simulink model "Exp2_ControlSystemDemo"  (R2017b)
settings: Solver=ode4  StartTime=0.0  StopTime=2000  FixedStep=0.001  RelTol=1e-3
PreLoadFcn:
  | filepath  = fileparts(get_param(bdroot, 'FileName'))
  | cd(filepath);
InitFcn:
  | if exist('Init_control.m','file')
  |      Init_control;
  | end
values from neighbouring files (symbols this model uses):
  KiPitchAttitude = 0.0552303199591522 / kFactor    (= 0.0460252666326)    [Init_control.m]
  KiPitchRate = 0.460338699849681 / kFactor    (= 0.383615583208)    [Init_control.m]
  KiRollAttitude = 0.0552303199591522 / kFactor    (= 0.0460252666326)    [Init_control.m]
  KiRollRate = 0.460338699849681 / kFactor    (= 0.383615583208)    [Init_control.m]
  KiYawRate = 0.460338699849681 / kFactor * 2    (= 0.767231166416)    [Init_control.m]
  KpPitchAttitude = 0.630138625117681 / kFactor    (= 0.525115520931)    [Init_control.m]
  KpPitchRate = 1.31533836563383 / kFactor    (= 1.09611530469)    [Init_control.m]
  KpRollAttitude = 0.630138625117681 / kFactor    (= 0.525115520931)    [Init_control.m]
  KpRollRate = 1.31533836563383 / kFactor    (= 1.09611530469)    [Init_control.m]
  KpYawRate = 1.31533836563383 / kFactor * 2    (= 2.19223060939)    [Init_control.m]
  ModelInit_RPM = 0    [Init.m]
  ModelParam_envAltitude = -50    [Init.m]
  ModelParam_GlobalNoiseGainSwitch = 0.4    [Init.m]
  ModelParam_GPSEphFinal = 0.3    [Init.m]
  ModelParam_GPSEpvFinal = 0.4    [Init.m]
  ModelParam_GPSFix3DFix = 3    [Init.m]
  ModelParam_GPSSatsVisible = 10    [Init.m]
  ModelParam_motorCr = 842.1    [Init.m]
  ModelParam_motorJm = 0.0001287    [Init.m]
  ModelParam_motorMinThr = 0.05    [Init.m]
  ModelParam_motorT = 0.0214    [Init.m]
  ModelParam_motorWb = 22.83    [Init.m]
  ModelParam_noiseBaroCoupleWithSpeed = 0    [Init.m]
  ModelParam_noiseGPSSampTime = 0.2    [Init.m]
  ModelParam_noisePowerIMU = 0    [Init.m]
  ModelParam_noisePowerOffGainAccel = 0.04    [Init.m]
  ModelParam_noisePowerOffGainAccelZ = 0.03    [Init.m]
  ModelParam_noisePowerOffGainGyro = 0.02    [Init.m]
  ModelParam_noisePowerOffGainGyroZ = 0.025    [Init.m]
  ModelParam_noisePowerOffGainMag = 0.02    [Init.m]
  ModelParam_noisePowerOffGainMagZ = 0.035    [Init.m]
  ModelParam_noisePowerOnGainAccel = 0.8    [Init.m]
  ModelParam_noisePowerOnGainAccelZ = 4.5    [Init.m]
  ModelParam_noisePowerOnGainGyro = 2    [Init.m]
  ModelParam_noisePowerOnGainGyroZ = 1    [Init.m]
  ModelParam_noisePowerOnGainMag = 0.025    [Init.m]
  ModelParam_noisePowerOnGainMagZ = 0.05    [Init.m]
  ModelParam_noiseSampleTimeAccel = 0.001    [Init.m]
  ModelParam_noiseSampleTimeGyro = 0.001    [Init.m]
  ModelParam_noiseSampleTimeMag = 0.01    [Init.m]
  ModelParam_noiseUpperGPS = 0.5    [Init.m]
  ModelParam_noiseUpperWindBodyRatio = 0    [Init.m]
  ModelParam_noiseWindSampTime = 0.001    [Init.m]
  ModelParam_rotorCm = 2.783e-07    [Init.m]
  ModelParam_rotorCt = 1.681e-05    [Init.m]
  ModelParam_timeSampBaro = 0.01    [Init.m]
  ModelParam_uavCCm = [0.0035 0.0039 0.0034]    [Init.m]
  ModelParam_uavCd = 0.055    [Init.m]
  ModelParam_uavDearo = 0.12    [Init.m]
  ModelParam_uavMass = 1.515    [Init.m]
  ModelParam_uavR = 0.225    [Init.m]
  ModelParam_uavType = int8(3)    [Init.m]
undefined symbols (not defined in the file or in its folder): a029, a452, a6b4, b2ca, be23, d291, d_i, da57f061, e227219c210b, e95a516b5039, Earth, earthRadius, Exp2_ControlSystemDemo, f0d8, f8138af1, ff54be59cd06, h_i, ModelParam_GPSEpvInitial, ModelParam_GPSEpvTimeConstant, ModelParam_noiseLowPassFilterCoeAccel, ModelParam_noiseLowPassFilterCoeGyro, ModelParam_timeSamp, Newton, Raphson, Receive, Send, slider, WGS84
libraries: simulink x17, aerolibfltsims x4, aerolibtransform2 x3, sharedtransform x3, aerolibasang x3, aerolibatmos2 x2, sharedutil x2, aerolibutil x2, etargetslib x2, shared6dof x1, aerolibconvert2 x1, aerolibobsolete x1
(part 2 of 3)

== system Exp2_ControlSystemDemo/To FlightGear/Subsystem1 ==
  copterID : Inport  PortDimensions=1
  vehicleType : Inport  Port=2  PortDimensions=1
  PosE : Inport  Port=3  PortDimensions=3
  AngEuler : Inport  Port=4  PortDimensions=3
  pwms : Inport  Port=5
  Clock : Clock
  Constant{,3..5} (4 alike) : Constant  Value=[0,0,0]
  Constant1 : Constant  Value=[0,0,0,0]
  Subsystem : Subsystem
  toUnReal : Outport
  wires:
  Constant/1 -> Subsystem/4("VelE ")
  PosE/1 -> Subsystem/5(PosE)
  vehicleType/1 -> Subsystem/2(vehicleType)
  Clock/1 -> Subsystem/3(runnedTime)
  Constant4/1 -> Subsystem/10(RateB)
  Constant5/1 -> Subsystem/11(PosGPS)
  AngEuler/1 -> Subsystem/6(AngEuler)
  Subsystem/1(toUnReal) -> toUnReal/1
  Constant3/1 -> Subsystem/9(AccB)
  Constant1/1 -> Subsystem/7(AngQuatern)
  copterID/1 -> Subsystem/1(copterID)
  pwms/1 -> Subsystem/8(MotorRPMS)

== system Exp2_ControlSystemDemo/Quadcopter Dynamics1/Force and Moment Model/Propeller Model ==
  uavType : Inport
  MotorRads : Inport  Port=2
  uavR : Inport  Port=3
  uavDearo : Inport  Port=4
  Cm : Inport  Port=5
  Ct : Inport  Port=6
  Jm : Inport  Port=7
  wb : Inport  Port=8
  Vb : Inport  Port=9
  Cd : Inport  Port=10
  Car : Subsystem  TreatAsAtomicUnit=on
  If : If  IfExpression=u1 >= 50
  Multicopter : Subsystem  TreatAsAtomicUnit=on
  Switch : Switch  Threshold=50
  Switch1 : Switch  Threshold=50
  Terminator : Terminator
  Terminator1 : Terminator
  Fb : Outport
  Mb : Outport  Port=2
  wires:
  Vb/1 -> Terminator/1
  Cd/1 -> Terminator1/1
  uavType/1 -> If/1, Switch/2, Switch1/2, Multicopter/1(uavType)
  Switch/1 -> Fb/1
  Switch1/1 -> Mb/1
  If/2 -> Multicopter/Action
  If/1 -> Car/Action
  Car/1(Fb) -> Switch/1
  Multicopter/1(Fb) -> Switch/3
  Car/2(Mb) -> Switch1/1
  Multicopter/2(Mb) -> Switch1/3
  MotorRads/1 -> Car/1(MotorRads), Multicopter/2(MotorRads)
  uavDearo/1 -> Multicopter/4(uavDearo)
  Cm/1 -> Multicopter/5(Cm)
  Ct/1 -> Multicopter/6(Ct)
  Jm/1 -> Multicopter/7(Jm)
  wb/1 -> Multicopter/8(wb)
  uavR/1 -> Multicopter/3(uavR)

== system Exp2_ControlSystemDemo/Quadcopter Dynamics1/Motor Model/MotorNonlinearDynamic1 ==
  Wb : Inport
  Cr : Inport  Port=2
  motorT : Inport  Port=3
  ModelInit_RPM : Inport  Port=4
  PWM : Inport  Port=5
  Minimum Throttle Cutoff : simulink/Logic and Bit Operations/Compare To Constant  relop=>=  const=ModelParam_motorMinThr  OutDataTypeStr=uint8
  Motor_Dynamics : Subsystem  TreatAsAtomicUnit=on
  Motor_Dynamics_backup : StateSpace  Commented=on  A=-1/ModelParam_motorT  C=1/ModelParam_motorT  D=0  InitialCondition=ModelInit_RPM*ModelParam_motorT
  Product : Product
  Product1 : Product
  Signal_Saturation : Saturate  UpperLimit=0.95  LowerLimit=0
  Sum1 : Sum  Inputs=++|
  radW : Outport
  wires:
  PWM/1 -> Signal_Saturation/1
  Motor_Dynamics/1(motor_rate_act) -> radW/1
  Product/1 -> Motor_Dynamics/1(motor_rate_d)
  Signal_Saturation/1 -> Product1/2, Minimum Throttle Cutoff/1
  Product1/1 -> Sum1/2
  Sum1/1 -> Product/1
  Wb/1 -> Sum1/1
  Minimum Throttle Cutoff/1 -> Product/2
  Cr/1 -> Product1/1
  motorT/1 -> Motor_Dynamics/3(motorT)
  ModelInit_RPM/1 -> Motor_Dynamics/2(ModelInit_RPM)

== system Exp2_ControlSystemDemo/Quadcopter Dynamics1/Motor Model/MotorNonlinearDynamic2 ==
  Wb : Inport
  Cr : Inport  Port=2
  motorT : Inport  Port=3
  ModelInit_RPM : Inport  Port=4
  PWM : Inport  Port=5
  Minimum Throttle Cutoff : simulink/Logic and Bit Operations/Compare To Constant  relop=>=  const=ModelParam_motorMinThr  OutDataTypeStr=uint8
  Motor_Dynamics : Subsystem  TreatAsAtomicUnit=on
  Motor_Dynamics_backup : StateSpace  Commented=on  A=-1/ModelParam_motorT  C=1/ModelParam_motorT  D=0  InitialCondition=ModelInit_RPM*ModelParam_motorT
  Product : Product
  Product1 : Product
  Signal_Saturation : Saturate  UpperLimit=0.95  LowerLimit=0
  Sum1 : Sum  Inputs=++|
  radW : Outport
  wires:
  ModelInit_RPM/1 -> Motor_Dynamics/2(ModelInit_RPM)
  motorT/1 -> Motor_Dynamics/3(motorT)
  Cr/1 -> Product1/1
  Minimum Throttle Cutoff/1 -> Product/2
  Wb/1 -> Sum1/1
  Sum1/1 -> Product/1
  Product1/1 -> Sum1/2
  Signal_Saturation/1 -> Minimum Throttle Cutoff/1, Product1/2
  Product/1 -> Motor_Dynamics/1(motor_rate_d)
  Motor_Dynamics/1(motor_rate_act) -> radW/1
  PWM/1 -> Signal_Saturation/1

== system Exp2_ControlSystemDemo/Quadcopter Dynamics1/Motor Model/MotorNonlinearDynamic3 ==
  Wb : Inport
  Cr : Inport  Port=2
  motorT : Inport  Port=3
  ModelInit_RPM : Inport  Port=4
  PWM : Inport  Port=5
  Minimum Throttle Cutoff : simulink/Logic and Bit Operations/Compare To Constant  relop=>=  const=ModelParam_motorMinThr  OutDataTypeStr=uint8
  Motor_Dynamics : Subsystem  TreatAsAtomicUnit=on
  Motor_Dynamics_backup : StateSpace  Commented=on  A=-1/ModelParam_motorT  C=1/ModelParam_motorT  D=0  InitialCondition=ModelInit_RPM*ModelParam_motorT
  Product : Product
  Product1 : Product
  Signal_Saturation : Saturate  UpperLimit=0.95  LowerLimit=0
  Sum1 : Sum  Inputs=++|
  radW : Outport
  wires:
  PWM/1 -> Signal_Saturation/1
  Motor_Dynamics/1(motor_rate_act) -> radW/1
  Product/1 -> Motor_Dynamics/1(motor_rate_d)
  Signal_Saturation/1 -> Product1/2, Minimum Throttle Cutoff/1
  Product1/1 -> Sum1/2
  Sum1/1 -> Product/1
  Wb/1 -> Sum1/1
  Minimum Throttle Cutoff/1 -> Product/2
  Cr/1 -> Product1/1
  motorT/1 -> Motor_Dynamics/3(motorT)
  ModelInit_RPM/1 -> Motor_Dynamics/2(ModelInit_RPM)

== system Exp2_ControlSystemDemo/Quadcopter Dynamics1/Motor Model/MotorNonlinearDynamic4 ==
  Wb : Inport
  Cr : Inport  Port=2
  motorT : Inport  Port=3
  ModelInit_RPM : Inport  Port=4
  PWM : Inport  Port=5
  Minimum Throttle Cutoff : simulink/Logic and Bit Operations/Compare To Constant  relop=>=  const=ModelParam_motorMinThr  OutDataTypeStr=uint8
  Motor_Dynamics : Subsystem  TreatAsAtomicUnit=on
  Motor_Dynamics_backup : StateSpace  Commented=on  A=-1/ModelParam_motorT  C=1/ModelParam_motorT  D=0  InitialCondition=ModelInit_RPM*ModelParam_motorT
  Product : Product
  Product1 : Product
  Signal_Saturation : Saturate  UpperLimit=0.95  LowerLimit=0
  Sum1 : Sum  Inputs=++|
  radW : Outport
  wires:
  ModelInit_RPM/1 -> Motor_Dynamics/2(ModelInit_RPM)
  motorT/1 -> Motor_Dynamics/3(motorT)
  Cr/1 -> Product1/1
  Minimum Throttle Cutoff/1 -> Product/2
  Wb/1 -> Sum1/1
  Sum1/1 -> Product/1
  Product1/1 -> Sum1/2
  Signal_Saturation/1 -> Minimum Throttle Cutoff/1, Product1/2
  Product/1 -> Motor_Dynamics/1(motor_rate_d)
  Motor_Dynamics/1(motor_rate_act) -> radW/1
  PWM/1 -> Signal_Saturation/1

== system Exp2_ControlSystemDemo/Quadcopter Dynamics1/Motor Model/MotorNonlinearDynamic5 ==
  Wb : Inport
  Cr : Inport  Port=2
  motorT : Inport  Port=3
  ModelInit_RPM : Inport  Port=4
  PWM : Inport  Port=5
  Minimum Throttle Cutoff : simulink/Logic and Bit Operations/Compare To Constant  relop=>=  const=ModelParam_motorMinThr  OutDataTypeStr=uint8
  Motor_Dynamics : Subsystem  TreatAsAtomicUnit=on
  Motor_Dynamics_backup : StateSpace  Commented=on  A=-1/ModelParam_motorT  C=1/ModelParam_motorT  D=0  InitialCondition=ModelInit_RPM*ModelParam_motorT
  Product : Product
  Product1 : Product
  Signal_Saturation : Saturate  UpperLimit=0.95  LowerLimit=0
  Sum1 : Sum  Inputs=++|
  radW : Outport
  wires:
  PWM/1 -> Signal_Saturation/1
  Motor_Dynamics/1(motor_rate_act) -> radW/1
  Product/1 -> Motor_Dynamics/1(motor_rate_d)
  Signal_Saturation/1 -> Product1/2, Minimum Throttle Cutoff/1
  Product1/1 -> Sum1/2
  Sum1/1 -> Product/1
  Wb/1 -> Sum1/1
  Minimum Throttle Cutoff/1 -> Product/2
  Cr/1 -> Product1/1
  motorT/1 -> Motor_Dynamics/3(motorT)
  ModelInit_RPM/1 -> Motor_Dynamics/2(ModelInit_RPM)

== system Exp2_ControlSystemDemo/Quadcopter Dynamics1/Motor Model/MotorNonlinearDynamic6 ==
  Wb : Inport
  Cr : Inport  Port=2
  motorT : Inport  Port=3
  ModelInit_RPM : Inport  Port=4
  PWM : Inport  Port=5
  Minimum Throttle Cutoff : simulink/Logic and Bit Operations/Compare To Constant  relop=>=  const=ModelParam_motorMinThr  OutDataTypeStr=uint8
  Motor_Dynamics : Subsystem  TreatAsAtomicUnit=on
  Motor_Dynamics_backup : StateSpace  Commented=on  A=-1/ModelParam_motorT  C=1/ModelParam_motorT  D=0  InitialCondition=ModelInit_RPM*ModelParam_motorT
  Product : Product
  Product1 : Product
  Signal_Saturation : Saturate  UpperLimit=0.95  LowerLimit=0
  Sum1 : Sum  Inputs=++|
  radW : Outport
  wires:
  ModelInit_RPM/1 -> Motor_Dynamics/2(ModelInit_RPM)
  motorT/1 -> Motor_Dynamics/3(motorT)
  Cr/1 -> Product1/1
  Minimum Throttle Cutoff/1 -> Product/2
  Wb/1 -> Sum1/1
  Sum1/1 -> Product/1
  Product1/1 -> Sum1/2
  Signal_Saturation/1 -> Minimum Throttle Cutoff/1, Product1/2
  Product/1 -> Motor_Dynamics/1(motor_rate_d)
  Motor_Dynamics/1(motor_rate_act) -> radW/1
  PWM/1 -> Signal_Saturation/1

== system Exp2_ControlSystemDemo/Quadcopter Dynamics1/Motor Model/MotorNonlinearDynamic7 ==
  Wb : Inport
  Cr : Inport  Port=2
  motorT : Inport  Port=3
  ModelInit_RPM : Inport  Port=4
  PWM : Inport  Port=5
  Minimum Throttle Cutoff : simulink/Logic and Bit Operations/Compare To Constant  relop=>=  const=ModelParam_motorMinThr  OutDataTypeStr=uint8
  Motor_Dynamics : Subsystem  TreatAsAtomicUnit=on
  Motor_Dynamics_backup : StateSpace  Commented=on  A=-1/ModelParam_motorT  C=1/ModelParam_motorT  D=0  InitialCondition=ModelInit_RPM*ModelParam_motorT
  Product : Product
  Product1 : Product
  Signal_Saturation : Saturate  UpperLimit=0.95  LowerLimit=0
  Sum1 : Sum  Inputs=++|
  radW : Outport
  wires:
  PWM/1 -> Signal_Saturation/1
  Motor_Dynamics/1(motor_rate_act) -> radW/1
  Product/1 -> Motor_Dynamics/1(motor_rate_d)
  Signal_Saturation/1 -> Product1/2, Minimum Throttle Cutoff/1
  Product1/1 -> Sum1/2
  Sum1/1 -> Product/1
  Wb/1 -> Sum1/1
  Minimum Throttle Cutoff/1 -> Product/2
  Cr/1 -> Product1/1
  motorT/1 -> Motor_Dynamics/3(motorT)
  ModelInit_RPM/1 -> Motor_Dynamics/2(ModelInit_RPM)

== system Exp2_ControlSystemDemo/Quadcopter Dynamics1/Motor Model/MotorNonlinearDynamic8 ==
  Wb : Inport
  Cr : Inport  Port=2
  motorT : Inport  Port=3
  ModelInit_RPM : Inport  Port=4
  PWM : Inport  Port=5
  Minimum Throttle Cutoff : simulink/Logic and Bit Operations/Compare To Constant  relop=>=  const=ModelParam_motorMinThr  OutDataTypeStr=uint8
  Motor_Dynamics : Subsystem  TreatAsAtomicUnit=on
  Motor_Dynamics_backup : StateSpace  Commented=on  A=-1/ModelParam_motorT  C=1/ModelParam_motorT  D=0  InitialCondition=ModelInit_RPM*ModelParam_motorT
  Product : Product
  Product1 : Product
  Signal_Saturation : Saturate  UpperLimit=0.95  LowerLimit=0
  Sum1 : Sum  Inputs=++|
  radW : Outport
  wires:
  ModelInit_RPM/1 -> Motor_Dynamics/2(ModelInit_RPM)
  motorT/1 -> Motor_Dynamics/3(motorT)
  Cr/1 -> Product1/1
  Minimum Throttle Cutoff/1 -> Product/2
  Wb/1 -> Sum1/1
  Sum1/1 -> Product/1
  Product1/1 -> Sum1/2
  Signal_Saturation/1 -> Minimum Throttle Cutoff/1, Product1/2
  Product/1 -> Motor_Dynamics/1(motor_rate_d)
  Motor_Dynamics/1(motor_rate_act) -> radW/1
  PWM/1 -> Signal_Saturation/1

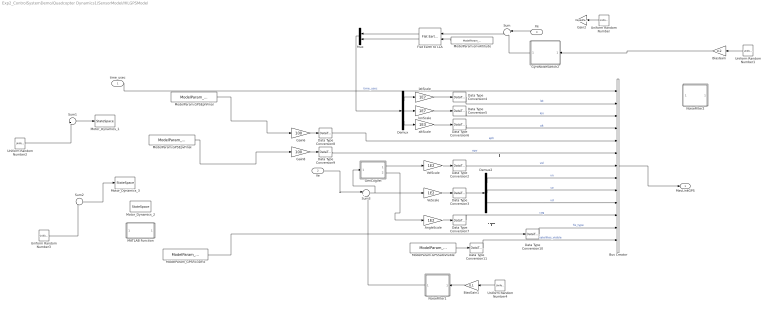
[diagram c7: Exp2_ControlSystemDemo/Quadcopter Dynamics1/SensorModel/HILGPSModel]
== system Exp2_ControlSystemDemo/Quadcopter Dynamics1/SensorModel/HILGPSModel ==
  note: 水平速度
  note: 运动方位
  time_usec : Inport
  Ve : Inport  Port=2
  Xe : Inport  Port=3
  AngleScale : Gain  Gain=1E2
  BiasGain : Gain  Gain=0.2
  BiasGain1 : Gain  Gain=0.1
  Bus Creator : BusCreator  Inputs=13  OutDataTypeStr=Bus: MavLinkGPS
  Data Type Conversion10 : DataTypeConversion  OutDataTypeStr=uint8  RndMeth=Round
  Data Type Conversion11 : DataTypeConversion  OutDataTypeStr=uint8  RndMeth=Round
  Data Type Conversion{2,7..9} (4 alike) : DataTypeConversion  OutDataTypeStr=uint16  RndMeth=Round
  Data Type Conversion3 : DataTypeConversion  OutDataTypeStr=int16  RndMeth=Round
  Data Type Conversion4 : DataTypeConversion  OutDataTypeStr=int32  RndMeth=Round
  Data Type Conversion5 : DataTypeConversion  OutDataTypeStr=int32  RndMeth=Round
  Data Type Conversion6 : DataTypeConversion  OutDataTypeStr=int32  RndMeth=Round
  Demux : Demux  Outputs=3
  Demux2 : Demux  Outputs=3
  Flat Earth to LLA : aerolibtransform2/Flat Earth to LLA  units=Metric (MKS)  ptype=Earth (WGS84)  F=1/298.257223563  R=6378137  LL0=ModelParam_GPSLatLong  psi=0
  Gain2 : Gain  Commented=on  Gain=ModelParam_noiseUpperGPS
  Gain6 : Gain  Gain=100
  Gain8 : Gain  Gain=100
  GenCogVel : MATLAB Function  TreatAsAtomicUnit=on
  GyroNoiseSwitch2 : Subsystem
  MATLAB Function : MATLAB Function  Commented=on  TreatAsAtomicUnit=on
  ModelParam.GPSEphFinal : Constant  Value=ModelParam_GPSEphFinal
  ModelParam.GPSEpvFinal : Constant  Value=ModelParam_GPSEpvFinal
  ModelParam.GPSSatsVisible : Constant  Value=ModelParam_GPSSatsVisible
  ModelParam.envAltitude : Constant  Value=ModelParam_envAltitude
  ModelParam_GPSFix3DFix : Constant  Value=ModelParam_GPSFix3DFix
  Motor_Dynamics_1 : StateSpace  Commented=on  A=-1/0.2  C=1/0.2  D=0  InitialCondition=20*0.2
  Motor_Dynamics_2 : StateSpace  Commented=on  A=-1/ModelParam_GPSEpvTimeConstant  C=1/ModelParam_GPSEpvTimeConstant  D=0  InitialCondition=ModelParam_GPSEpvInitial*ModelParam_GPSEpvTimeConstant
  Motor_Dynamics_3 : StateSpace  Commented=on  A=-1/0.2  C=1/0.2  D=0  InitialCondition=20*0.2
  Mux : Mux  Inputs=2
  NoiseFilter1 : Subsystem
  NoiseFilter2 : Subsystem  Commented=on
  Sum : Sum  Inputs=|++
  Sum1 : Sum  Commented=on  Inputs=|++
  Sum2 : Sum  Commented=on  Inputs=|++
  Sum3 : Sum  Inputs=|++
  Uniform Random Number : UniformRandomNumber  Commented=on  Minimum=[-1,-1,-3]  Maximum=[1,1,3]  Seed=[14524,7875,698]  SampleTime=ModelParam_timeSamp
  Uniform Random Number1 : UniformRandomNumber  Minimum=[-1,-1,-2]  Maximum=[1,1,2]  Seed=[1452,787,69]  SampleTime=ModelParam_noiseGPSSampTime
  Uniform Random Number2 : UniformRandomNumber  Commented=on  Minimum=-0.01  Maximum=0.01  Seed=4345454  SampleTime=ModelParam_noiseGPSSampTime
  Uniform Random Number3 : UniformRandomNumber  Commented=on  Seed=3244333  SampleTime=ModelParam_noiseGPSSampTime
  Uniform Random Number4 : UniformRandomNumber  Minimum=[-1,-1,-2]  Maximum=[1,1,2]  Seed=[5445,45433,33433]  SampleTime=ModelParam_noiseGPSSampTime
  VeScale : Gain  Gain=1E2
  VelScale : Gain  Gain=1E2
  altScale : Gain  Gain=1E3
  latScale : Gain  Gain=1E7
  lonScale : Gain  Gain=1E7
  MavLinkGPS : Outport
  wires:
  Data Type Conversion8/1 -> Bus Creator/5  "eph"
  Gain8/1 -> Data Type Conversion9/1
  Gain6/1 -> Data Type Conversion8/1
  Data Type Conversion9/1 -> Bus Creator/6  "epv"
  time_usec/1 -> Bus Creator/1  "time_usec"
  latScale/1 -> Data Type Conversion4/1
  lonScale/1 -> Data Type Conversion5/1
  altScale/1 -> Data Type Conversion6/1
  Data Type Conversion4/1 -> Bus Creator/2  "lat"
  Data Type Conversion5/1 -> Bus Creator/3  "lon"
  Data Type Conversion6/1 -> Bus Creator/4  "alt"
  Demux2/1 -> Bus Creator/8  "vn"
  Demux2/2 -> Bus Creator/9  "ve"
  Demux2/3 -> Bus Creator/10  "vd"
  VeScale/1 -> Data Type Conversion3/1
  Data Type Conversion3/1 -> Demux2/1
  VelScale/1 -> Data Type Conversion2/1
  Data Type Conversion2/1 -> Bus Creator/7  "vel"
  AngleScale/1 -> Data Type Conversion7/1
  Data Type Conversion7/1 -> Bus Creator/11  "cog"
  Data Type Conversion11/1 -> Bus Creator/13  "satellites_visible"
  Data Type Conversion10/1 -> Bus Creator/12  "fix_type"
  ModelParam.GPSSatsVisible/1 -> Data Type Conversion11/1
  Flat Earth to LLA/2 -> Mux/2
  ModelParam.envAltitude/1 -> Flat Earth to LLA/2
  Xe/1 -> Sum/1
  Flat Earth to LLA/1 -> Mux/1
  Demux/1 -> latScale/1
  Demux/2 -> lonScale/1
  Demux/3 -> altScale/1
  Uniform Random Number/1 -> Gain2/1
  Sum/1 -> Flat Earth to LLA/1
  Uniform Random Number1/1 -> BiasGain/1
  BiasGain/1 -> GyroNoiseSwitch2/1(In1)
  Mux/1 -> Demux/1
  ModelParam.GPSEphFinal/1 -> Gain6/1
  Sum2/1 -> Motor_Dynamics_3/1
  ModelParam_GPSFix3DFix/1 -> Data Type Conversion10/1
  Ve/1 -> Sum3/1
  GenCogVel/1(v) -> VelScale/1
  GyroNoiseSwitch2/1(Out1) -> Sum/2
  Bus Creator/1 -> MavLinkGPS/1
  BiasGain1/1 -> NoiseFilter1/1(In1)
  Uniform Random Number4/1 -> BiasGain1/1
  GenCogVel/2(cot) -> AngleScale/1
  Sum1/1 -> Motor_Dynamics_1/1
  Uniform Random Number2/1 -> Sum1/2
  Uniform Random Number3/1 -> Sum2/2
  ModelParam.GPSEpvFinal/1 -> Gain8/1
  Sum3/1 -> GenCogVel/1(u), VeScale/1
  NoiseFilter1/1(Out1) -> Sum3/2

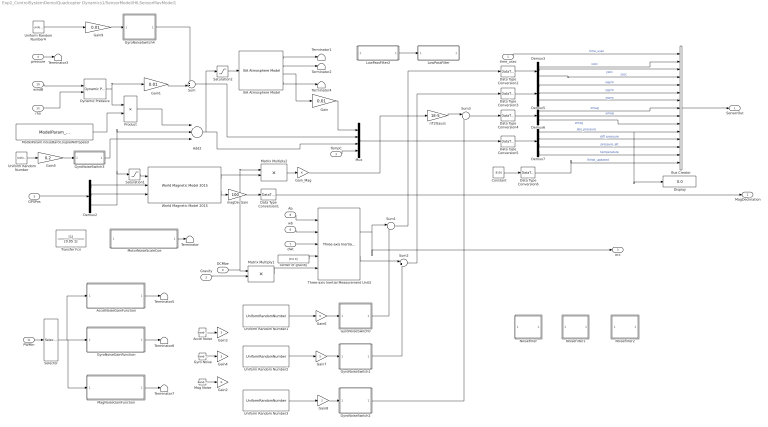
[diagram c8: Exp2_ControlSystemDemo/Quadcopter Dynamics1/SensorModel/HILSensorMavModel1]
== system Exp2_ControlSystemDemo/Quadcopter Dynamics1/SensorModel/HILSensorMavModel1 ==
  time_usec : Inport
  Gravity : Inport  Port=2
  TempC : Inport  Port=3
  pressure : Inport  Port=4
  GPSPos : Inport  Port=5
  wb : Inport  Port=6
  dwt : Inport  Port=7
  Ab : Inport  Port=8
  DCMbe : Inport  Port=9
  windB : Inport  Port=10
  PWMin : Inport  Port=11
  rho : Inport  Port=12
  Accel Noise : simulink/Sources/Band-Limited White Noise  Commented=on  Cov=ModelParam_noisePowerAccel  Ts=ModelParam_noiseSampleTimeAccel  seed=[411144,1416,71144]
  AccelNoiseGainFunction : MATLAB Function  TreatAsAtomicUnit=on
  Add2 : Sum  Inputs=+++
  Bus Creator : BusCreator  Inputs=15  OutDataTypeStr=Bus: MavLinkSensor
  Constant : Constant  Value=8191
  Data Type Conversion1 : DataTypeConversion  OutDataTypeStr=int16
  Data Type Conversion{2..5} (4 alike) : DataTypeConversion  OutDataTypeStr=single
  Data Type Conversion6 : DataTypeConversion  OutDataTypeStr=uint32
  Demux{2..3,5..6} (4 alike) : Demux  Outputs=3
  Demux7 : Demux
  Display : Display
  Dynamic Pressure : aerolibasang/Dynamic Pressure
  Gain : Gain  Gain=0.01
  Gain1 : Gain  Gain=0.01
  Gain2 : Gain  Commented=on
  Gain3 : Gain  Commented=on  Gain=3
  Gain4 : Gain  Commented=on  Gain=3
  Gain5 : Gain  Gain=0.2
  Gain6 : Gain  Gain=5
  Gain7 : Gain  Gain=5
  Gain8 : Gain  Gain=2
  Gain9 : Gain  Gain=0.01
  Gain_Mag : Gain
  Gyro Noise : simulink/Sources/Band-Limited White Noise  Commented=on  Cov=ModelParam_noisePowerGyro  Ts=ModelParam_noiseSampleTimeGyro  seed=[111,116,144]
  GyroNoiseGainFunction : MATLAB Function  TreatAsAtomicUnit=on
  GyroNoiseSwitch0 : Subsystem
  GyroNoiseSwitch1 : Subsystem
  GyroNoiseSwitch2 : Subsystem
  GyroNoiseSwitch3 : Subsystem
  GyroNoiseSwitch4 : Subsystem
  ISA Atmosphere Model : aerolibatmos2/ISA Atmosphere Model  custom=off  g=9.80665  gamma=1.4  R=287.0531  L=0.0065  h_trop=11000  h_strat=20000  rho0=1.225  P0=101325  T0=288.15  h0=0
  LowPassFilter : Subsystem  Commented=on
  LowPassFilter2 : Subsystem  Commented=on
  Mag Noise : simulink/Sources/Band-Limited White Noise  Commented=on  Cov=ModelParam_noisePowerMag  Ts=ModelParam_noiseSampleTimeMag  seed=[114,11699,999144]
  MagNoiseGainFunction : MATLAB Function  TreatAsAtomicUnit=on
  Matrix Multiply1 : Product  Multiplication=Matrix(*)
  Matrix Multiply2 : Product  Multiplication=Matrix(*)
  ModelParam.noiseBaroCoupleWithSpeed : Constant  Value=ModelParam_noiseBaroCoupleWithSpeed
  MotorNoiseScaleCoe : MATLAB Function  Commented=on  TreatAsAtomicUnit=on
  Mux : Mux
  NoiseFilter : Subsystem  Commented=on
  NoiseFilter1 : Subsystem  Commented=on
  NoiseFilter2 : Subsystem  Commented=on
  Product : Product
  Saturation1 : Saturate  UpperLimit=100000  LowerLimit=0
  Saturation2 : Saturate  UpperLimit=100000  LowerLimit=0
  Selector : Selector  InputPortWidth=8  IndexOptions=Index vector (dialog)  Indices=[1]  OutputSizes=1
  Sum : Sum  Inputs=++|
  Sum1 : Sum  Inputs=|++
  Sum2 : Sum  Inputs=|++
  Sum3 : Sum  Inputs=|++
  Terminator{,1..7} (8 alike) : Terminator
  Three-axis Inertial Measurement Unit3 : aerolibnav/Three-axis Inertial Measurement Unit  units=Metric (MKS)  imu=[0 0 0]  i_Ts=0  dtype_a=on  w_a=190  z_a=0.707  a_sf_cc=[1 0 0; 0 1 0; 0 0 1]  a_bias=[0 0 0]  a_sat="[-160  -160  -160 160 160 160]"  dtype_g=on  w_g=190  z_g=0.707  g_sf_cc=[1 0 0; 0 1 0; 0 0 1]  g_bias=[0 0 0]  g_sens=[0 0 0]  g_sat="[-4.36  -4.36  -4.36 4.36 4.36 4.36]"  i_rand=off  i_seeds=[23093 23094 23095 23096 23097 23098]  i_pow=ModelParam_noisePowerIMU*[0.0000005 0.0000005 0.0000005 0.000000002 0.000000002 0.000000002]
  Transfer Fcn : TransferFcn  Commented=on  Denominator=[0.05 1]
  Uniform Random Number : UniformRandomNumber  Minimum=-2  Maximum=2  Seed=15634  SampleTime=ModelParam_timeSampBaro
  Uniform Random Number1 : UniformRandomNumber  Minimum=-[0.1,0.1,0.2]  Maximum=[0.1,0.1,0.2]  Seed=[12233,645554,678766]  SampleTime=0.004
  Uniform Random Number2 : UniformRandomNumber  Minimum=-[0.01,0.01,0.01]  Maximum=[0.01,0.01,0.01]  Seed=[3243,44556,2334343]  SampleTime=0.004
  Uniform Random Number3 : UniformRandomNumber  Minimum=-[0.01,0.01,0.01]  Maximum=[0.01,0.01,0.01]  Seed=[45465,454534,1234232]  SampleTime=0.004
  Uniform Random Number4 : UniformRandomNumber  Seed=25634  SampleTime=0.01
  World Magnetic Model 2015 : aerolibgravity2/World Magnetic Model 2015  units=Metric (MKS)  time_in=off  month=November  day=3  year=2017  action=Error  h_out=off  dec_out=on  inc_out=off  ti_out=off
  center of gravity : Constant  Value=[0 0 0]
  magDecGain : Gain  Gain=100
  nT2Gauss : Gain  Gain=1E-5
  SensorOut : Outport
  MagDeclination : Outport  Port=2
  acc : Outport  Port=3
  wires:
  center of gravity/1 -> Three-axis Inertial Measurement Unit3/4
  Sum1/1 -> Data Type Conversion2/1
  Sum2/1 -> Data Type Conversion3/1
  Sum3/1 -> Data Type Conversion4/1
  Matrix Multiply2/1 -> Gain_Mag/1
  magDecGain/1 -> Data Type Conversion1/1
  World Magnetic Model 2015/2 -> magDecGain/1
  GyroNoiseSwitch3/1(Out1) -> Add2/3
  Product/1 -> Add2/1
  ModelParam.noiseBaroCoupleWithSpeed/1 -> Product/2
  rho/1 -> Dynamic Pressure/2
  windB/1 -> Dynamic Pressure/1
  Uniform Random Number/1 -> Gain5/1
  dwt/1 -> Three-axis Inertial Measurement Unit3/3
  Gain_Mag/1 -> nT2Gauss/1
  Dynamic Pressure/1 -> Gain1/1, Product/1
  pressure/1 -> Terminator3/1
  Add2/1 -> Mux/3, Saturation2/1
  Demux2/3 -> Saturation1/1, Add2/2
  Demux2/2 -> World Magnetic Model 2015/3
  Demux2/1 -> World Magnetic Model 2015/2
  Matrix Multiply1/1 -> Three-axis Inertial Measurement Unit3/5
  DCMbe/1 -> Matrix Multiply2/1, Matrix Multiply1/1
  Gravity/1 -> Matrix Multiply1/2
  Sum/1 -> Mux/2
  Gain/1 -> Mux/1
  Data Type Conversion6/1 -> Bus Creator/15  "fields_updated"
  Constant/1 -> Data Type Conversion6/1
  time_usec/1 -> Bus Creator/1  "time_usec"
  GPSPos/1 -> Demux2/1
  Demux7/2 -> Bus Creator/12  "diff_pressure"
  Demux7/3 -> Bus Creator/13  "pressure_alt"
  Demux6/2 -> Bus Creator/9  "ymag"
  Demux6/3 -> Bus Creator/10  "zmag"
  TempC/1 -> Mux/4
  Mux/1 -> Data Type Conversion5/1
  Demux7/1 -> Bus Creator/11, Display/1  "abs_pressure"
  Demux5/2 -> Bus Creator/6  "ygyro"
  Demux6/1 -> Bus Creator/8  "xmag"
  Demux5/3 -> Bus Creator/7  "zgyro"
  Demux7/4 -> Bus Creator/14  "temperature"
  World Magnetic Model 2015/1 -> Matrix Multiply2/2
  Demux3/1 -> Bus Creator/2  "xacc"
  Demux3/2 -> Bus Creator/3  "yacc"
  Demux5/1 -> Bus Creator/5  "xgyro"
  Demux3/3 -> Bus Creator/4  "zacc"
  PWMin/1 -> Selector/1
  Ab/1 -> Three-axis Inertial Measurement Unit3/1
  wb/1 -> Three-axis Inertial Measurement Unit3/2
  MotorNoiseScaleCoe/1(NoiseScaleCoe) -> Terminator/1
  Selector/1 -> AccelNoiseGainFunction/1(theta), MagNoiseGainFunction/1(theta), GyroNoiseGainFunction/1(theta)
  AccelNoiseGainFunction/1(Gain) -> Terminator5/1
  Mag Noise/1 -> Gain2/1
  nT2Gauss/1 -> Sum3/1
  Gain8/1 -> GyroNoiseSwitch2/1(In1)
  GyroNoiseSwitch1/1(Out1) -> Sum2/2
  GyroNoiseSwitch2/1(Out1) -> Sum3/2
  Data Type Conversion2/1 -> Demux3/1
  Data Type Conversion3/1 -> Demux5/1
  Data Type Conversion4/1 -> Demux6/1
  Data Type Conversion5/1 -> Demux7/1
  Bus Creator/1 -> SensorOut/1
  Data Type Conversion1/1 -> MagDeclination/1
  Three-axis Inertial Measurement Unit3/1 -> acc/1, Sum1/1
  Three-axis Inertial Measurement Unit3/2 -> Sum2/1
  ISA Atmosphere Model/2 -> Terminator2/1
  ISA Atmosphere Model/4 -> Terminator4/1
  ISA Atmosphere Model/1 -> Terminator1/1
  Gain5/1 -> GyroNoiseSwitch3/1(In1)
  Accel Noise/1 -> Gain3/1
  GyroNoiseSwitch0/1(Out1) -> Sum1/2
  Gyro Noise/1 -> Gain4/1
  GyroNoiseGainFunction/1(Gain) -> Terminator6/1
  MagNoiseGainFunction/1(Gain) -> Terminator7/1
  Uniform Random Number1/1 -> Gain6/1
  Gain7/1 -> GyroNoiseSwitch1/1(In1)
  Uniform Random Number2/1 -> Gain7/1
  Uniform Random Number3/1 -> Gain8/1
  ISA Atmosphere Model/3 -> Gain/1
  Gain6/1 -> GyroNoiseSwitch0/1(In1)
  LowPassFilter2/1(accelDataOut) -> LowPassFilter/1(gyroDataIn)
  Gain9/1 -> GyroNoiseSwitch4/1(In1)
  Uniform Random Number4/1 -> Gain9/1
  Gain1/1 -> Sum/2
  GyroNoiseSwitch4/1(Out1) -> Sum/1
  Saturation1/1 -> World Magnetic Model 2015/1
  Saturation2/1 -> ISA Atmosphere Model/1

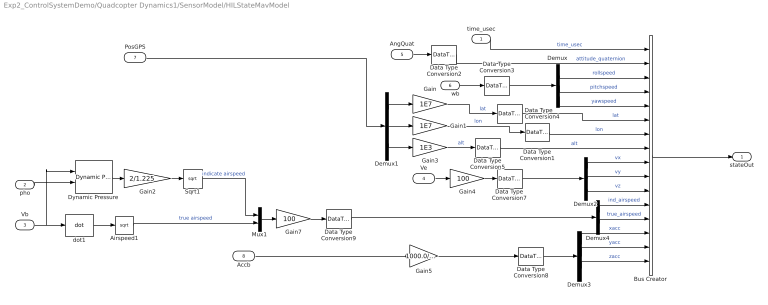
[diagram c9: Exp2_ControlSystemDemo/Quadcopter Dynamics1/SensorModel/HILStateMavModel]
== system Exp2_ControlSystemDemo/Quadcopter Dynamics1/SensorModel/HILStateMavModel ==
  time_usec : Inport
  pho : Inport  Port=2
  Vb : Inport  Port=3
  Ve : Inport  Port=4
  AngQuat : Inport  Port=5
  wb : Inport  Port=6
  PosGPS : Inport  Port=7
  Accb : Inport  Port=8
  Airspeed1 : Sqrt  AlgorithmType=Newton-Raphson
  Bus Creator : BusCreator  Inputs=16  OutDataTypeStr=Bus: MavLinkStateQuat
  Data Type Conversion1 : DataTypeConversion  OutDataTypeStr=int32  RndMeth=Round
  Data Type Conversion2 : DataTypeConversion  OutDataTypeStr=single
  Data Type Conversion3 : DataTypeConversion  OutDataTypeStr=single
  Data Type Conversion4 : DataTypeConversion  OutDataTypeStr=int32  RndMeth=Round
  Data Type Conversion5 : DataTypeConversion  OutDataTypeStr=int32  RndMeth=Round
  Data Type Conversion7 : DataTypeConversion  OutDataTypeStr=int16  RndMeth=Round
  Data Type Conversion8 : DataTypeConversion  OutDataTypeStr=int16  RndMeth=Round
  Data Type Conversion9 : DataTypeConversion  OutDataTypeStr=uint16  RndMeth=Round
  Demux{,1..3} (4 alike) : Demux  Outputs=3
  Demux4 : Demux  Outputs=2
  Dynamic Pressure : aerolibasang/Dynamic Pressure
  Gain : Gain  Gain=1E7
  Gain1 : Gain  Gain=1E7
  Gain2 : Gain  Gain=2/1.225
  Gain3 : Gain  Gain=1E3
  Gain4 : Gain  Gain=100
  Gain5 : Gain  Gain=1000.0/9.80665
  Gain7 : Gain  Gain=100
  Mux1 : Mux  Inputs=2
  Sqrt1 : Sqrt
  dot1 : aerolibasang/Incidence, Sideslip, & Airspeed/dot
  stateOut : Outport
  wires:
  Sqrt1/1 -> Mux1/1  "indicate airspeed"
  Gain2/1 -> Sqrt1/1
  Dynamic Pressure/1 -> Gain2/1
  time_usec/1 -> Bus Creator/1  "time_usec"
  Vb/1 -> dot1/1, Dynamic Pressure/1
  AngQuat/1 -> Data Type Conversion2/1
  Ve/1 -> Gain4/1
  wb/1 -> Data Type Conversion3/1
  Airspeed1/1 -> Mux1/2  "true airspeed"
  Mux1/1 -> Gain7/1
  Demux4/1 -> Bus Creator/12  "ind_airspeed"
  Demux4/2 -> Bus Creator/13  "true_airspeed"
  Demux3/3 -> Bus Creator/16  "zacc"
  Demux3/2 -> Bus Creator/15  "yacc"
  Demux3/1 -> Bus Creator/14  "xacc"
  Gain5/1 -> Data Type Conversion8/1
  Accb/1 -> Gain5/1
  Demux2/3 -> Bus Creator/11  "vz"
  Demux2/2 -> Bus Creator/10  "vy"
  Demux2/1 -> Bus Creator/9  "vx"
  Gain4/1 -> Data Type Conversion7/1
  Gain3/1 -> Data Type Conversion5/1  "alt"
  Gain1/1 -> Data Type Conversion1/1  "lon"
  Gain/1 -> Data Type Conversion4/1  "lat"
  Demux1/3 -> Gain3/1
  Demux1/2 -> Gain1/1
  Demux1/1 -> Gain/1
  Demux/3 -> Bus Creator/5  "yawspeed"
  Demux/2 -> Bus Creator/4  "pitchspeed"
  Demux/1 -> Bus Creator/3  "rollspeed"
  Data Type Conversion2/1 -> Bus Creator/2  "attitude_quaternion"
  pho/1 -> Dynamic Pressure/2
  Gain7/1 -> Data Type Conversion9/1
  dot1/1 -> Airspeed1/1
  Data Type Conversion3/1 -> Demux/1
  Data Type Conversion7/1 -> Demux2/1
  Data Type Conversion9/1 -> Demux4/1
  Data Type Conversion8/1 -> Demux3/1
  Data Type Conversion4/1 -> Bus Creator/6  "lat"
  Data Type Conversion1/1 -> Bus Creator/7  "lon"
  Data Type Conversion5/1 -> Bus Creator/8  "alt"
  Bus Creator/1 -> stateOut/1
  PosGPS/1 -> Demux1/1

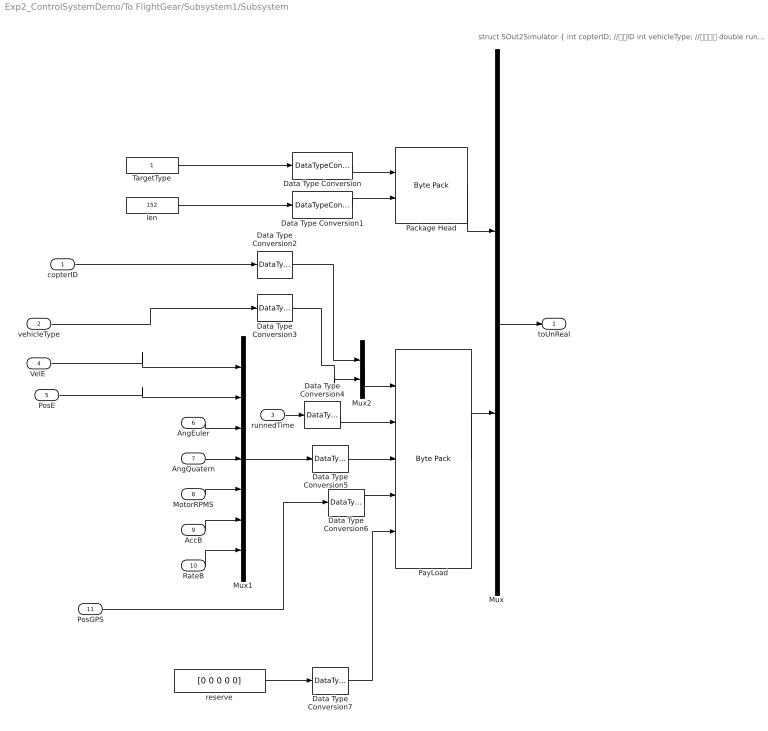
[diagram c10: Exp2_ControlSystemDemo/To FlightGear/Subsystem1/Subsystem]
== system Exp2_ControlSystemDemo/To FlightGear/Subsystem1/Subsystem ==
  note: struct SOut2Simulator { int copterID; //飞机ID int vehicleType; //飞机构型 double runnedTime; //仿真时间 float VelE[3]; //NED地球系速度 float PosE[3]; //NED地球系位置 float AngEuler[3]; //欧拉角 float AngQuatern[4]; //四元数 float MotorRPMS[8]; //电机转速RPM float AccB[3]; //机体轴加速度 float RateB[3]; //机体轴角速度 double PosGPS[3]; //地球GPS经纬高 } //SOut2Simulator的定义与Simulink里面新加的MavVehileInfo结构体完全一致 //可以直接对新的simulink模型的MavVehile3DInfo输出口数据进行打包 //两个结构体的长度都是152 sizeof(SOut2Simulator) = sizeof(MavVehileInfo) = 152 打包封装的结构体为 typedef struct _netDataShort { TargetType tg; //这里目前随便填，写1即可 uint32 int len; //这个长度为传输结构体长度，目前是152 char payload[192]; //这里面前152位存放了SOut2Simulator结构体数据，后面的40位保留 }netDataShort; //UDP包的总长度为200 sizeof(netDataShort) = 200 //发送的UDP端口号为：20010
  copterID : Inport  PortDimensions=1
  vehicleType : Inport  Port=2  PortDimensions=1
  runnedTime : Inport  Port=3  PortDimensions=1
  "VelE " : Inport  Port=4  PortDimensions=3
  PosE : Inport  Port=5  PortDimensions=3
  AngEuler : Inport  Port=6  PortDimensions=3
  AngQuatern : Inport  Port=7  PortDimensions=4
  MotorRPMS : Inport  Port=8  PortDimensions=8
  AccB : Inport  Port=9  PortDimensions=3
  RateB : Inport  Port=10  PortDimensions=3
  PosGPS : Inport  Port=11  PortDimensions=3
  Data Type Conversion : DataTypeConversion  OutDataTypeStr=uint32
  Data Type Conversion1 : DataTypeConversion  OutDataTypeStr=int32
  Data Type Conversion2 : DataTypeConversion  OutDataTypeStr=int32
  Data Type Conversion3 : DataTypeConversion  OutDataTypeStr=int32
  Data Type Conversion4 : DataTypeConversion  OutDataTypeStr=double
  Data Type Conversion5 : DataTypeConversion  OutDataTypeStr=single
  Data Type Conversion6 : DataTypeConversion  OutDataTypeStr=double
  Data Type Conversion7 : DataTypeConversion  OutDataTypeStr=double
  Mux : Mux  Inputs=2
  Mux1 : Mux  Inputs=7
  Mux2 : Mux  Inputs=2
  Package Head : etargetslib/Byte Pack  datatypes={'uint32','int32'}  byteAlign=4
  PayLoad : etargetslib/Byte Pack  datatypes={'int32','double','single','double','double'}  byteAlign=8
  TargetType : Constant  OutDataTypeStr=Inherit: Inherit via back propagation
  len : Constant  Value=152  OutDataTypeStr=Inherit: Inherit via back propagation
  reserve : Constant  Value=[0 0 0 0 0]  OutDataTypeStr=double
  toUnReal : Outport
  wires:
  runnedTime/1 -> Data Type Conversion4/1
  RateB/1 -> Mux1/7
  PayLoad/1 -> Mux/2
  "VelE "/1 -> Mux1/1
  Mux1/1 -> Data Type Conversion5/1
  PosGPS/1 -> Data Type Conversion6/1
  Package Head/1 -> Mux/1
  AccB/1 -> Mux1/6
  Mux/1 -> toUnReal/1
  MotorRPMS/1 -> Mux1/5
  AngQuatern/1 -> Mux1/4
  copterID/1 -> Data Type Conversion2/1
  len/1 -> Data Type Conversion1/1
  vehicleType/1 -> Data Type Conversion3/1
  PosE/1 -> Mux1/2
  TargetType/1 -> Data Type Conversion/1
  reserve/1 -> Data Type Conversion7/1
  Mux2/1 -> PayLoad/1
  AngEuler/1 -> Mux1/3
  Data Type Conversion5/1 -> PayLoad/3
  Data Type Conversion2/1 -> Mux2/1
  Data Type Conversion1/1 -> Package Head/2
  Data Type Conversion6/1 -> PayLoad/4
  Data Type Conversion/1 -> Package Head/1
  Data Type Conversion3/1 -> Mux2/2
  Data Type Conversion4/1 -> PayLoad/2
  Data Type Conversion7/1 -> PayLoad/5

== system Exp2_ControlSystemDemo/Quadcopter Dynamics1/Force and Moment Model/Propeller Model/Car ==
  MotorRads : Inport
  Action Port : ActionPort  InitializeStates=reset
  MATLAB Function : MATLAB Function  TreatAsAtomicUnit=on
  Fb : Outport
  Mb : Outport  Port=2
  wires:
  MATLAB Function/1(Fb) -> Fb/1
  MATLAB Function/2(Mb) -> Mb/1
  MotorRads/1 -> MATLAB Function/1(MotorRads)

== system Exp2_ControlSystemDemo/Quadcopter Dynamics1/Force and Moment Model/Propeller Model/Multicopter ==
  uavType : Inport
  MotorRads : Inport  Port=2
  uavR : Inport  Port=3
  uavDearo : Inport  Port=4
  Cm : Inport  Port=5
  Ct : Inport  Port=6
  Jm : Inport  Port=7
  wb : Inport  Port=8
  Action Port : ActionPort  InitializeStates=reset
  For Iterator Subsystem : Subsystem  TreatAsAtomicUnit=on
  Gain : Gain  Gain=-1
  Vector Concatenate : Concatenate
  Vector Concatenate1 : Concatenate  NumInputs=3  Mode=Multidimensional array
  motorPhiVector : Constant  Commented=on
  motorPsiVector : Constant  Commented=on
  motorRotateDirectionVector : Constant  Commented=on
  motorThetaVector : Constant  Commented=on
  n_p : Constant  Commented=on
  uavTypeDefine : MATLAB Function  TreatAsAtomicUnit=on
  Fb : Outport
  Mb : Outport  Port=2
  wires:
  wb/1 -> For Iterator Subsystem/2(wb)
  uavR/1 -> Vector Concatenate/1
  uavDearo/1 -> Gain/1
  Gain/1 -> Vector Concatenate/2
  Vector Concatenate/1 -> For Iterator Subsystem/4(motorPositionVector)
  MotorRads/1 -> For Iterator Subsystem/5(motorOmegaVector)
  Cm/1 -> For Iterator Subsystem/9(rotorCm)
  Ct/1 -> For Iterator Subsystem/8(rotorCt)
  Jm/1 -> For Iterator Subsystem/6(motorJ_RP)
  For Iterator Subsystem/2(Mb) -> Mb/1
  For Iterator Subsystem/1(Fb) -> Fb/1
  uavType/1 -> uavTypeDefine/1(uavType)
  uavTypeDefine/1(n_p) -> For Iterator Subsystem/1(n_p)
  uavTypeDefine/5(motorRotateDirectionVector) -> For Iterator Subsystem/7(motorRotateDirectionVector)
  uavTypeDefine/4(motorPsiVector) -> Vector Concatenate1/3
  uavTypeDefine/3(motorThetaVector) -> Vector Concatenate1/2
  uavTypeDefine/2(motorPhiVector) -> Vector Concatenate1/1
  Vector Concatenate1/1 -> For Iterator Subsystem/3(motorEularMatrix)

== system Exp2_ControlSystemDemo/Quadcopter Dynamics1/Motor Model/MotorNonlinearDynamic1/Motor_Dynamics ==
  motor_rate_d : Inport
  ModelInit_RPM : Inport  Port=2
  motorT : Inport  Port=3
  Add : Sum  Inputs=+-
  Divide : Product  Inputs=*/
  Integrator : Integrator  InitialConditionSource=external
  motor_rate_act : Outport
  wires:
  motorT/1 -> Divide/2
  Integrator/1 -> Add/2, motor_rate_act/1  "x"
  Divide/1 -> Integrator/1  "drate/dt"
  motor_rate_d/1 -> Add/1
  ModelInit_RPM/1 -> Integrator/2
  Add/1 -> Divide/1

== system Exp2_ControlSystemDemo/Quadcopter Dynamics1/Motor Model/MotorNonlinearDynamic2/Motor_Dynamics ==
  motor_rate_d : Inport
  ModelInit_RPM : Inport  Port=2
  motorT : Inport  Port=3
  Add : Sum  Inputs=+-
  Divide : Product  Inputs=*/
  Integrator : Integrator  InitialConditionSource=external
  motor_rate_act : Outport
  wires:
  Add/1 -> Divide/1
  ModelInit_RPM/1 -> Integrator/2
  motor_rate_d/1 -> Add/1
  Divide/1 -> Integrator/1  "drate/dt"
  Integrator/1 -> motor_rate_act/1, Add/2  "x"
  motorT/1 -> Divide/2

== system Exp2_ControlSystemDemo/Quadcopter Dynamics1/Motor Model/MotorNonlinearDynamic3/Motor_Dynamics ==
  motor_rate_d : Inport
  ModelInit_RPM : Inport  Port=2
  motorT : Inport  Port=3
  Add : Sum  Inputs=+-
  Divide : Product  Inputs=*/
  Integrator : Integrator  InitialConditionSource=external
  motor_rate_act : Outport
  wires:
  motorT/1 -> Divide/2
  Integrator/1 -> Add/2, motor_rate_act/1  "x"
  Divide/1 -> Integrator/1  "drate/dt"
  motor_rate_d/1 -> Add/1
  ModelInit_RPM/1 -> Integrator/2
  Add/1 -> Divide/1

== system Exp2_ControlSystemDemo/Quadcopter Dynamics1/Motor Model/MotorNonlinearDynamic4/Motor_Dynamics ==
  motor_rate_d : Inport
  ModelInit_RPM : Inport  Port=2
  motorT : Inport  Port=3
  Add : Sum  Inputs=+-
  Divide : Product  Inputs=*/
  Integrator : Integrator  InitialConditionSource=external
  motor_rate_act : Outport
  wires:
  Add/1 -> Divide/1
  ModelInit_RPM/1 -> Integrator/2
  motor_rate_d/1 -> Add/1
  Divide/1 -> Integrator/1  "drate/dt"
  Integrator/1 -> motor_rate_act/1, Add/2  "x"
  motorT/1 -> Divide/2

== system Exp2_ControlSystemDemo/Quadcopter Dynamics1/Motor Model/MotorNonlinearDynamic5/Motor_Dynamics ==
  motor_rate_d : Inport
  ModelInit_RPM : Inport  Port=2
  motorT : Inport  Port=3
  Add : Sum  Inputs=+-
  Divide : Product  Inputs=*/
  Integrator : Integrator  InitialConditionSource=external
  motor_rate_act : Outport
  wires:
  motorT/1 -> Divide/2
  Integrator/1 -> Add/2, motor_rate_act/1  "x"
  Divide/1 -> Integrator/1  "drate/dt"
  motor_rate_d/1 -> Add/1
  ModelInit_RPM/1 -> Integrator/2
  Add/1 -> Divide/1

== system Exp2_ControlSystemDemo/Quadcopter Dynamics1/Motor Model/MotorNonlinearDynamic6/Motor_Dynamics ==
  motor_rate_d : Inport
  ModelInit_RPM : Inport  Port=2
  motorT : Inport  Port=3
  Add : Sum  Inputs=+-
  Divide : Product  Inputs=*/
  Integrator : Integrator  InitialConditionSource=external
  motor_rate_act : Outport
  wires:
  Add/1 -> Divide/1
  ModelInit_RPM/1 -> Integrator/2
  motor_rate_d/1 -> Add/1
  Divide/1 -> Integrator/1  "drate/dt"
  Integrator/1 -> motor_rate_act/1, Add/2  "x"
  motorT/1 -> Divide/2

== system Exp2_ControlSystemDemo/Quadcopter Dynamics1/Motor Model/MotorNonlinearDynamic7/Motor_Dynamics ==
  motor_rate_d : Inport
  ModelInit_RPM : Inport  Port=2
  motorT : Inport  Port=3
  Add : Sum  Inputs=+-
  Divide : Product  Inputs=*/
  Integrator : Integrator  InitialConditionSource=external
  motor_rate_act : Outport
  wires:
  motorT/1 -> Divide/2
  Integrator/1 -> Add/2, motor_rate_act/1  "x"
  Divide/1 -> Integrator/1  "drate/dt"
  motor_rate_d/1 -> Add/1
  ModelInit_RPM/1 -> Integrator/2
  Add/1 -> Divide/1

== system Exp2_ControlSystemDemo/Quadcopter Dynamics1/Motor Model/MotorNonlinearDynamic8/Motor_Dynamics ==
  motor_rate_d : Inport
  ModelInit_RPM : Inport  Port=2
  motorT : Inport  Port=3
  Add : Sum  Inputs=+-
  Divide : Product  Inputs=*/
  Integrator : Integrator  InitialConditionSource=external
  motor_rate_act : Outport
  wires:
  Add/1 -> Divide/1
  ModelInit_RPM/1 -> Integrator/2
  motor_rate_d/1 -> Add/1
  Divide/1 -> Integrator/1  "drate/dt"
  Integrator/1 -> motor_rate_act/1, Add/2  "x"
  motorT/1 -> Divide/2

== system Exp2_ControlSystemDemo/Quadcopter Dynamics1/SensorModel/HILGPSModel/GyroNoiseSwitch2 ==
  In1 : Inport
  Constant1 : Constant  Value=ModelParam_GlobalNoiseGainSwitch
  Constant2 : Constant  Value=0.3
  Gain2 : Gain  Gain=0.7
  Product4 : Product
  Sum : Sum  Inputs=|++
  Out1 : Outport
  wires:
  Sum/1 -> Product4/2
  Product4/1 -> Out1/1
  Gain2/1 -> Sum/1
  In1/1 -> Product4/1
  Constant1/1 -> Gain2/1
  Constant2/1 -> Sum/2

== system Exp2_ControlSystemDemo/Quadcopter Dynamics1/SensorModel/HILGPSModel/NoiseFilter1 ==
  In1 : Inport
  Demux : Demux  Outputs=3
  Mux1 : Mux  Inputs=3
  Transfer Fcn1 : TransferFcn  Denominator=[0.05 1]
  Transfer Fcn2 : TransferFcn  Denominator=[0.05 1]
  Transfer Fcn4 : TransferFcn  Denominator=[0.05 1]
  Out1 : Outport
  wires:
  Mux1/1 -> Out1/1
  In1/1 -> Demux/1
  Demux/3 -> Transfer Fcn2/1
  Transfer Fcn4/1 -> Mux1/1
  Transfer Fcn2/1 -> Mux1/3
  Demux/1 -> Transfer Fcn4/1
  Transfer Fcn1/1 -> Mux1/2
  Demux/2 -> Transfer Fcn1/1

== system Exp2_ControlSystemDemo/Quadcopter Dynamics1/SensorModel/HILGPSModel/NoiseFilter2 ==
  In1 : Inport
  Demux : Demux  Outputs=3
  Mux1 : Mux  Inputs=3
  Transfer Fcn1 : TransferFcn  Denominator=[0.05 1]
  Transfer Fcn2 : TransferFcn  Denominator=[0.05 1]
  Transfer Fcn4 : TransferFcn  Denominator=[0.05 1]
  Out1 : Outport
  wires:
  Mux1/1 -> Out1/1
  In1/1 -> Demux/1
  Demux/3 -> Transfer Fcn2/1
  Transfer Fcn4/1 -> Mux1/1
  Transfer Fcn2/1 -> Mux1/3
  Demux/1 -> Transfer Fcn4/1
  Transfer Fcn1/1 -> Mux1/2
  Demux/2 -> Transfer Fcn1/1

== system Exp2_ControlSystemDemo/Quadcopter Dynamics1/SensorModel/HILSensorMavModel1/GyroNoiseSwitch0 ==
  In1 : Inport
  Constant1 : Constant  Value=ModelParam_GlobalNoiseGainSwitch
  Constant2 : Constant  Value=0.2
  Gain2 : Gain  Gain=0.8
  Product4 : Product
  Sum : Sum  Inputs=|++
  Out1 : Outport
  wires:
  Sum/1 -> Product4/2
  Product4/1 -> Out1/1
  Gain2/1 -> Sum/1
  In1/1 -> Product4/1
  Constant1/1 -> Gain2/1
  Constant2/1 -> Sum/2

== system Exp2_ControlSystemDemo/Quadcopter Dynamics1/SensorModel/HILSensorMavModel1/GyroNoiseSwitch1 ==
  In1 : Inport
  Constant1 : Constant  Value=ModelParam_GlobalNoiseGainSwitch
  Constant2 : Constant  Value=0.2
  Gain2 : Gain  Gain=0.8
  Product4 : Product
  Sum : Sum  Inputs=|++
  Out1 : Outport
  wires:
  Sum/1 -> Product4/2
  Product4/1 -> Out1/1
  Gain2/1 -> Sum/1
  In1/1 -> Product4/1
  Constant1/1 -> Gain2/1
  Constant2/1 -> Sum/2

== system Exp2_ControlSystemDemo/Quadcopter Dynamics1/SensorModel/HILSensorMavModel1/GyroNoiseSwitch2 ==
  In1 : Inport
  Constant1 : Constant  Value=ModelParam_GlobalNoiseGainSwitch
  Constant2 : Constant  Value=0.2
  Gain2 : Gain  Gain=0.8
  Product4 : Product
  Sum : Sum  Inputs=|++
  Out1 : Outport
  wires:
  Sum/1 -> Product4/2
  Product4/1 -> Out1/1
  Gain2/1 -> Sum/1
  In1/1 -> Product4/1
  Constant1/1 -> Gain2/1
  Constant2/1 -> Sum/2

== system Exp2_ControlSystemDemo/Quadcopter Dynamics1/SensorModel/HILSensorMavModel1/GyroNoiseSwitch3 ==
  In1 : Inport
  Constant1 : Constant  Value=ModelParam_GlobalNoiseGainSwitch
  Constant2 : Constant  Value=0.3
  Gain2 : Gain  Gain=0.7
  Product4 : Product
  Sum : Sum  Inputs=|++
  Out1 : Outport
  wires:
  Sum/1 -> Product4/2
  Product4/1 -> Out1/1
  Gain2/1 -> Sum/1
  In1/1 -> Product4/1
  Constant1/1 -> Gain2/1
  Constant2/1 -> Sum/2

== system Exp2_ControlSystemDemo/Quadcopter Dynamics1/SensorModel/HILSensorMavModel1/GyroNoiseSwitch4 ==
  In1 : Inport
  Constant1 : Constant  Value=ModelParam_GlobalNoiseGainSwitch
  Constant2 : Constant  Value=0.3
  Gain2 : Gain  Gain=0.7
  Product4 : Product
  Sum : Sum  Inputs=|++
  Out1 : Outport
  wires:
  Sum/1 -> Product4/2
  Product4/1 -> Out1/1
  Gain2/1 -> Sum/1
  In1/1 -> Product4/1
  Constant1/1 -> Gain2/1
  Constant2/1 -> Sum/2

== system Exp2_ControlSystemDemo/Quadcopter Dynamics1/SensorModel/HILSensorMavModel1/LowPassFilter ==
  gyroDataIn : Inport
  Demux1 : Demux  Outputs=3
  Mux1 : Mux  Inputs=3
  x : TransferFcn  Denominator=[ModelParam_noiseLowPassFilterCoeGyro 1]
  y : TransferFcn  Denominator=[ModelParam_noiseLowPassFilterCoeGyro 1]
  z : TransferFcn  Denominator=[ModelParam_noiseLowPassFilterCoeGyro 1]
  gyroDataOut : Outport
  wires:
  Mux1/1 -> gyroDataOut/1
  z/1 -> Mux1/3
  x/1 -> Mux1/1
  Demux1/1 -> x/1
  y/1 -> Mux1/2
  gyroDataIn/1 -> Demux1/1
  Demux1/2 -> y/1
  Demux1/3 -> z/1

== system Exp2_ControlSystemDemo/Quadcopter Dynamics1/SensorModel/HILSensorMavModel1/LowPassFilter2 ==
  accelDataIn : Inport
  Demux1 : Demux  Outputs=3
  Mux1 : Mux  Inputs=3
  x : TransferFcn  Denominator=[ModelParam_noiseLowPassFilterCoeAccel 1]
  y : TransferFcn  Denominator=[ModelParam_noiseLowPassFilterCoeAccel 1]
  z : TransferFcn  Denominator=[ModelParam_noiseLowPassFilterCoeAccel 1]
  accelDataOut : Outport
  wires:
  Mux1/1 -> accelDataOut/1
  z/1 -> Mux1/3
  x/1 -> Mux1/1
  Demux1/1 -> x/1
  y/1 -> Mux1/2
  accelDataIn/1 -> Demux1/1
  Demux1/2 -> y/1
  Demux1/3 -> z/1

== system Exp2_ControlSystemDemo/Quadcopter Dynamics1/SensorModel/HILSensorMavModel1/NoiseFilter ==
  In1 : Inport
  Demux : Demux  Outputs=3
  Mux1 : Mux  Inputs=3
  Transfer Fcn4 : TransferFcn  Denominator=[0.04 1]
  Transfer Fcn5 : TransferFcn  Denominator=[0.04 1]
  Transfer Fcn6 : TransferFcn  Denominator=[0.04 1]
  Out1 : Outport
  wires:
  Mux1/1 -> Out1/1
  In1/1 -> Demux/1
  Demux/3 -> Transfer Fcn6/1
  Transfer Fcn4/1 -> Mux1/1
  Transfer Fcn6/1 -> Mux1/3
  Demux/1 -> Transfer Fcn4/1
  Transfer Fcn5/1 -> Mux1/2
  Demux/2 -> Transfer Fcn5/1

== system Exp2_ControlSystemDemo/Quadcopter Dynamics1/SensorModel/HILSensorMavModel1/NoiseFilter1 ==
  In1 : Inport
  Demux : Demux  Outputs=3
  Mux1 : Mux  Inputs=3
  Transfer Fcn4 : TransferFcn  Denominator=[0.04 1]
  Transfer Fcn5 : TransferFcn  Denominator=[0.04 1]
  Transfer Fcn6 : TransferFcn  Denominator=[0.04 1]
  Out1 : Outport
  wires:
  Mux1/1 -> Out1/1
  In1/1 -> Demux/1
  Demux/3 -> Transfer Fcn6/1
  Transfer Fcn4/1 -> Mux1/1
  Transfer Fcn6/1 -> Mux1/3
  Demux/1 -> Transfer Fcn4/1
  Transfer Fcn5/1 -> Mux1/2
  Demux/2 -> Transfer Fcn5/1

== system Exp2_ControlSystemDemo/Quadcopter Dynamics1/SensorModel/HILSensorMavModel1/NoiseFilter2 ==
  In1 : Inport
  Demux : Demux  Outputs=3
  Mux1 : Mux  Inputs=3
  Transfer Fcn4 : TransferFcn  Denominator=[0.05 1]
  Transfer Fcn5 : TransferFcn  Denominator=[0.05 1]
  Transfer Fcn6 : TransferFcn  Denominator=[0.05 1]
  Out1 : Outport
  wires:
  Mux1/1 -> Out1/1
  In1/1 -> Demux/1
  Demux/3 -> Transfer Fcn6/1
  Transfer Fcn4/1 -> Mux1/1
  Transfer Fcn6/1 -> Mux1/3
  Demux/1 -> Transfer Fcn4/1
  Transfer Fcn5/1 -> Mux1/2
  Demux/2 -> Transfer Fcn5/1

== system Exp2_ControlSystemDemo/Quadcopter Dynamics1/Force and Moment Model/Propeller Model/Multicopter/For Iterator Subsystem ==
  note: 动力系统数量
  n_p : Inport
  wb : Inport  Port=2
  motorEularMatrix : Inport  Port=3
  motorPositionVector : Inport  Port=4
  motorOmegaVector : Inport  Port=5
  motorJ_RP : Inport  Port=6
  motorRotateDirectionVector : Inport  Port=7
  rotorCt : Inport  Port=8
  rotorCm : Inport  Port=9
  Add : Sum
  Add1 : Sum
  For Iterator : ForIterator  ResetStates=reset  IterationSource=external
  Memory : Memory  InitialCondition=[0;0;0]  InheritSampleTime=on
  Memory1 : Memory  InitialCondition=[0;0;0]  InheritSampleTime=on
  MotorForceAndMomentInAirFrame : Subsystem  mask(Multicopter_Force_and_Moment_Model){}
      mask help: 在模块上右键帮助,查看帮助文档
  Selector : Selector  InputPortWidth=8  IndexOptions=Index vector (port)  Indices=[1 3]  OutputSizes=1
  Selector1 : Selector  InputPortWidth=8  IndexOptions=Index vector (port)  Indices=[1 3]  OutputSizes=1
  Selector2 : Selector  NumberOfDimensions=2  InputPortWidth=8  IndexOptions=Select all,Index vector (port)  Indices=[1 3],1  OutputSizes=1,1
  Fb : Outport
  Mb : Outport  Port=2
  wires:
  n_p/1 -> For Iterator/1
  wb/1 -> MotorForceAndMomentInAirFrame/1(airframeOmega)
  motorPositionVector/1 -> MotorForceAndMomentInAirFrame/3(motorPositionInBodyFrame)
  rotorCm/1 -> MotorForceAndMomentInAirFrame/8(rotorCm)
  rotorCt/1 -> MotorForceAndMomentInAirFrame/7(rotorCt)
  motorJ_RP/1 -> MotorForceAndMomentInAirFrame/5(motorJ_RPi)
  For Iterator/1 -> Selector2/2, Selector1/2, Selector/2
  motorRotateDirectionVector/1 -> Selector/1
  Selector/1 -> MotorForceAndMomentInAirFrame/6(motorDelta_i)
  Selector1/1 -> MotorForceAndMomentInAirFrame/4(motorOmegai)
  motorOmegaVector/1 -> Selector1/1
  Selector2/1 -> MotorForceAndMomentInAirFrame/2(motorEularInBodyFrame)
  motorEularMatrix/1 -> Selector2/1
  MotorForceAndMomentInAirFrame/1(Fbi) -> Add/1
  Memory/1 -> Add/2
  Add/1 -> Fb/1, Memory/1
  MotorForceAndMomentInAirFrame/2(Mbi) -> Add1/1
  Memory1/1 -> Add1/2
  Add1/1 -> Mb/1, Memory1/1
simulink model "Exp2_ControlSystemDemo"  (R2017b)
settings: Solver=ode4  StartTime=0.0  StopTime=2000  FixedStep=0.001  RelTol=1e-3
PreLoadFcn:
  | filepath  = fileparts(get_param(bdroot, 'FileName'))
  | cd(filepath);
InitFcn:
  | if exist('Init_control.m','file')
  |      Init_control;
  | end
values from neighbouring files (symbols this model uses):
  KiPitchAttitude = 0.0552303199591522 / kFactor    (= 0.0460252666326)    [Init_control.m]
  KiPitchRate = 0.460338699849681 / kFactor    (= 0.383615583208)    [Init_control.m]
  KiRollAttitude = 0.0552303199591522 / kFactor    (= 0.0460252666326)    [Init_control.m]
  KiRollRate = 0.460338699849681 / kFactor    (= 0.383615583208)    [Init_control.m]
  KiYawRate = 0.460338699849681 / kFactor * 2    (= 0.767231166416)    [Init_control.m]
  KpPitchAttitude = 0.630138625117681 / kFactor    (= 0.525115520931)    [Init_control.m]
  KpPitchRate = 1.31533836563383 / kFactor    (= 1.09611530469)    [Init_control.m]
  KpRollAttitude = 0.630138625117681 / kFactor    (= 0.525115520931)    [Init_control.m]
  KpRollRate = 1.31533836563383 / kFactor    (= 1.09611530469)    [Init_control.m]
  KpYawRate = 1.31533836563383 / kFactor * 2    (= 2.19223060939)    [Init_control.m]
  ModelInit_RPM = 0    [Init.m]
  ModelParam_envAltitude = -50    [Init.m]
  ModelParam_GlobalNoiseGainSwitch = 0.4    [Init.m]
  ModelParam_GPSEphFinal = 0.3    [Init.m]
  ModelParam_GPSEpvFinal = 0.4    [Init.m]
  ModelParam_GPSFix3DFix = 3    [Init.m]
  ModelParam_GPSSatsVisible = 10    [Init.m]
  ModelParam_motorCr = 842.1    [Init.m]
  ModelParam_motorJm = 0.0001287    [Init.m]
  ModelParam_motorMinThr = 0.05    [Init.m]
  ModelParam_motorT = 0.0214    [Init.m]
  ModelParam_motorWb = 22.83    [Init.m]
  ModelParam_noiseBaroCoupleWithSpeed = 0    [Init.m]
  ModelParam_noiseGPSSampTime = 0.2    [Init.m]
  ModelParam_noisePowerIMU = 0    [Init.m]
  ModelParam_noisePowerOffGainAccel = 0.04    [Init.m]
  ModelParam_noisePowerOffGainAccelZ = 0.03    [Init.m]
  ModelParam_noisePowerOffGainGyro = 0.02    [Init.m]
  ModelParam_noisePowerOffGainGyroZ = 0.025    [Init.m]
  ModelParam_noisePowerOffGainMag = 0.02    [Init.m]
  ModelParam_noisePowerOffGainMagZ = 0.035    [Init.m]
  ModelParam_noisePowerOnGainAccel = 0.8    [Init.m]
  ModelParam_noisePowerOnGainAccelZ = 4.5    [Init.m]
  ModelParam_noisePowerOnGainGyro = 2    [Init.m]
  ModelParam_noisePowerOnGainGyroZ = 1    [Init.m]
  ModelParam_noisePowerOnGainMag = 0.025    [Init.m]
  ModelParam_noisePowerOnGainMagZ = 0.05    [Init.m]
  ModelParam_noiseSampleTimeAccel = 0.001    [Init.m]
  ModelParam_noiseSampleTimeGyro = 0.001    [Init.m]
  ModelParam_noiseSampleTimeMag = 0.01    [Init.m]
  ModelParam_noiseUpperGPS = 0.5    [Init.m]
  ModelParam_noiseUpperWindBodyRatio = 0    [Init.m]
  ModelParam_noiseWindSampTime = 0.001    [Init.m]
  ModelParam_rotorCm = 2.783e-07    [Init.m]
  ModelParam_rotorCt = 1.681e-05    [Init.m]
  ModelParam_timeSampBaro = 0.01    [Init.m]
  ModelParam_uavCCm = [0.0035 0.0039 0.0034]    [Init.m]
  ModelParam_uavCd = 0.055    [Init.m]
  ModelParam_uavDearo = 0.12    [Init.m]
  ModelParam_uavMass = 1.515    [Init.m]
  ModelParam_uavR = 0.225    [Init.m]
  ModelParam_uavType = int8(3)    [Init.m]
undefined symbols (not defined in the file or in its folder): a029, a452, a6b4, b2ca, be23, d291, d_i, da57f061, e227219c210b, e95a516b5039, Earth, earthRadius, Exp2_ControlSystemDemo, f0d8, f8138af1, ff54be59cd06, h_i, ModelParam_GPSEpvInitial, ModelParam_GPSEpvTimeConstant, ModelParam_noiseLowPassFilterCoeAccel, ModelParam_noiseLowPassFilterCoeGyro, ModelParam_timeSamp, Newton, Raphson, Receive, Send, slider, WGS84
libraries: simulink x17, aerolibfltsims x4, aerolibtransform2 x3, sharedtransform x3, aerolibasang x3, aerolibatmos2 x2, sharedutil x2, aerolibutil x2, etargetslib x2, shared6dof x1, aerolibconvert2 x1, aerolibobsolete x1
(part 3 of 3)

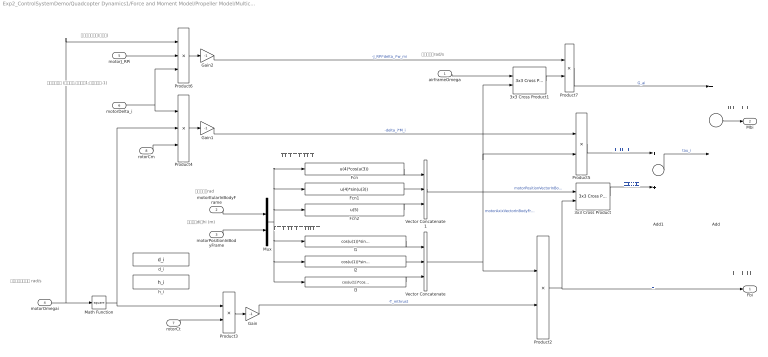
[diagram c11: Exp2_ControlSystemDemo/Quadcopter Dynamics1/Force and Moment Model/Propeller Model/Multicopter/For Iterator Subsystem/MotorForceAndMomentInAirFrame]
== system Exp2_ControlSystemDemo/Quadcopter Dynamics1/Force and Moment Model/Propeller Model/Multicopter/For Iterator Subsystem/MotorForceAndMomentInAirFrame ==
  note: 单个电机产生的力
  note: 单个电机产生的力矩
  note: 电机旋转方向 (俯视图下,顺时针为1;正逆时针为-1)
  note: 电机轴转动惯量(含桨叶)
  note: 机体角速度rad/s
  note: 电机轴转动角速度 rad/s
  note: 电机欧拉角rad
  note: 依次包含di和hi (m)
  note: 电机轴指向机体系正方向于机体系下的投影
  note: 电机位置在机体坐标系下的投影
  airframeOmega : Inport
  motorEularInBodyFrame : Inport  Port=2  PortDimensions=3
  motorPositionInBodyFrame : Inport  Port=3  PortDimensions=2
  motorOmegai : Inport  Port=4
  motorJ_RPi : Inport  Port=5
  motorDelta_i : Inport  Port=6
  rotorCt : Inport  Port=7
  rotorCm : Inport  Port=8
  3x3 Cross Product : sharedutil/3x3 Cross Product
  3x3 Cross Product1 : sharedutil/3x3 Cross Product
  Add : Sum  Inputs=2
  Add1 : Sum  Inputs=2
  Fcn : Fcn  Expr=u(4)*cos(u(3))
  Fcn1 : Fcn  Expr=u(4)*sin(u(3))
  Fcn2 : Fcn  Expr=u(5)
  Gain : Gain  Gain=-1
  Gain1 : Gain  Gain=-1
  Gain2 : Gain  Gain=-1
  Math Function : Math  Operator=square
  Mux : Mux  Inputs=2
  Product{2..3,5,7} (4 alike) : Product
  Product4 : Product  Inputs=3
  Product6 : Product  Inputs=3
  Vector Concatenate : Concatenate  NumInputs=3
  Vector Concatenate1 : Concatenate  NumInputs=3
  d_i : Constant  Commented=on  Value=d_i
  h_i : Constant  Commented=on  Value=h_i
  l1 : Fcn  Expr=cos(u(1))*sin(u(2))*cos(u(3)) + sin(u(1))*sin(u(3))
  l2 : Fcn  Expr=cos(u(1))*sin(u(2))*sin(u(3)) - sin(u(1))*cos(u(3))
  l3 : Fcn  Expr=cos(u(1))*cos(u(2))
  Fbi : Outport
  Mbi : Outport  Port=2
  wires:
  Mux/1 -> Fcn2/1, Fcn1/1, Fcn/1, l3/1, l2/1, l1/1
  motorEularInBodyFrame/1 -> Mux/1
  Product3/1 -> Gain/1
  Gain/1 -> Product2/2  "-T_mthrust"
  rotorCt/1 -> Product3/2
  Math Function/1 -> Product4/2, Product3/1
  Product2/1 -> Fbi/1, 3x3 Cross Product/2  "F_i"
  Vector Concatenate/1 -> Product2/1, 3x3 Cross Product1/2, Product5/2  "motorAxixVectorInBodyFrame"
  motorOmegai/1 -> Product6/1, Math Function/1
  rotorCm/1 -> Product4/3
  l1/1 -> Vector Concatenate/1
  Gain1/1 -> Product5/1  "-delta_i*M_i"
  Gain2/1 -> Product7/1  "-J_RPi*delta_i*w_mi"
  Add1/1 -> Add/2  "tau_i"
  3x3 Cross Product/1 -> Add1/2  "拉力产生的力矩"
  l2/1 -> Vector Concatenate/2
  Fcn2/1 -> Vector Concatenate1/3
  Add/1 -> Mbi/1
  l3/1 -> Vector Concatenate/3
  Fcn1/1 -> Vector Concatenate1/2
  Vector Concatenate1/1 -> 3x3 Cross Product/1  "motorPositionVectorInBodyFrame"
  Fcn/1 -> Vector Concatenate1/1
  motorDelta_i/1 -> Product6/3, Product4/1
  Product5/1 -> Add1/1  "反扭矩产生的力矩"
  3x3 Cross Product1/1 -> Product7/2
  Product6/1 -> Gain2/1
  airframeOmega/1 -> 3x3 Cross Product1/1
  Product4/1 -> Gain1/1
  motorJ_RPi/1 -> Product6/2
  Product7/1 -> Add/1  "G_ai"
  motorPositionInBodyFrame/1 -> Mux/2

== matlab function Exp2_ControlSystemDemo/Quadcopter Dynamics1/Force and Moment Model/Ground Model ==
function [F1,M1,landed,takeoff] = fcn(mg,wb,Xe,Ve,Quet,terrainZ)
% This is a ground model that can provides reaction force and reaction torque

% persistent z0;
% if isempty(z0)
%      z0=0;
% end

persistent takeoffFlag;
if isempty(takeoffFlag)
     takeoffFlag=int8(0);
end

persistent landFlag;
if isempty(landFlag)
     landFlag=int8(1);
end


z=Xe(3)-terrainZ;

 if (z<-0.3)&&(Ve(3)<-0.1)&&(takeoffFlag<0.5)
    takeoffFlag=int8(1);
    landFlag=int8(0);
 end
 
 if (z>-0.05)&&(Ve(3)>0.1)&&(landFlag<0.5)
    landFlag=int8(1);
    takeoffFlag=int8(0);
    %z0=terrainZ;
 end

takeoff = takeoffFlag;
landed = landFlag;


F1=[0;0;0];
M1=[0;0;0];

if z>=0
%     if z>=0.3
%         if Ve(3)>=5
%             F1(3)=-mg(3)-1000*Ve(3);
%         else
%             F1(3)=-mg(3)-500*z-100*Ve(3);  
%         end
%     elseif z>=0.1
%         if Ve(3)>=2
%             F1(3)=-mg(3)-100*Ve(3);
%         else
%             F1(3)=-mg(3)-50*z-100*Ve(3);  
%         end
%     else
%          if Ve(3)>=1
%             F1(3)=-mg(3)-50*Ve(3);
%         else
%             F1(3)=-mg(3)-5*z-50*Ve(3);  
%         end       
%     end
    if z<0.05
         F1(3)=-mg(3)-10*Ve(3); 
    elseif z<0.1
        F1(3)=-mg(3)-0.5*z-20*Ve(3); 
    else
         F1(3)=-mg(3)-1*z-50*Ve(3); 
    end

    
    F1(1)=-50*Ve(1);
    F1(2)=-50*Ve(2);
    M1=-20*[Quet(2);Quet(3);Quet(4)]-5*wb;
    M1 = M1 * abs(mg(3))*0.0333;
end

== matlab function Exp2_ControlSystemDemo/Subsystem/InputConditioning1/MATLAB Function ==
function y = fcn(u)
%将遥控输入的范围控制在1100~1900，同时设置一个死区，死区大小为±deadZone
RCMin = 1100;
RCMax = 1900;
deadZoneRate = 0.05;
deadZone = deadZoneRate*(RCMax-RCMin);
%限幅
if(u < RCMin)
    u = RCMin;
elseif(u > RCMax)
    u = RCMax;
end
%死区
 if(u > 1500+deadZone)
    y = u;
 elseif(u < 1500-deadZone)
     y = u;
 else
     y = 1500;
 end
     
 end

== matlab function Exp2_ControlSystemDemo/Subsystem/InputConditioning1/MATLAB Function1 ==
function y = fcn(u)
%将遥控输入的范围控制在1100~1900，同时设置一个死区，死区大小为±deadZone
RCMin = 1100;
RCMax = 1900;
deadZoneRate = 0.05;
deadZone = deadZoneRate*(RCMax-RCMin);
%限幅
if(u < RCMin)
    u = RCMin;
elseif(u > RCMax)
    u = RCMax;
end
%死区
 if(u > 1500+deadZone)
    y = u;
 elseif(u < 1500-deadZone)
     y = u;
 else
     y = 1500;
 end
     
 end

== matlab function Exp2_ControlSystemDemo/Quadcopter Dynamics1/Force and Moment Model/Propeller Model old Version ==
function [Fb,Mb] = fcn(uavType,MotorRads,R,uavDearo,Cm,Ct,Jm,wb,Vb,Cd)
% This is control effectiveness model, where Fb is the force produced by motors, Mb is
% the moment produced by motors, and Fd is the resistance produced by the air.
% The gyroscopic torque is not considered here.

% -1: anticlockwise, 1: clockwise 
TypeMotorDirMatrix=[...
    [-1 -1 -1 0 0 0 0 0];... % Tri 3*1 X
    [1 1 1 0 0 0 0 0];...    % Tri 3*1 +
    [-1 -1 1 1 0 0 0 0];... % Quad 4*1 X
    [-1 -1 1 1 0 0 0 0];... % Quad 4*1 +
    [1 -1 1 -1 -1 1 0 0];... % Hex 6*1 X
    [1 -1 1 -1 -1 1 0 0];... % Hex 6*1 +
    [1 -1 1 -1 1 -1 0 0];... % HexCoa 3*2
    [1 1 -1 -1 -1 -1 1 1];... % Oct 8*1 X
    [1 1 -1 -1 -1 -1 1 1];... % Oct 8*1 +
    [-1 1 -1 1 -1 1 -1 1];... % OctCoa 4*2 X
];

TypeMotorAngMatrix=[...
    [pi/3 pi -pi/3 0 0 0 0 0];...
    [pi/3 pi -pi/3 0 0 0 0 0];...
    [pi/4 pi/4+pi pi/4+3*pi/2 pi/4+pi/2 0 0 0 0];...
    [pi/2 3*pi/2 0 pi 0 0 0 0];...
    [pi/2 3/2*pi 3/2*pi+pi/3 pi/2+pi/3 pi/2-pi/3 3/2*pi-pi/3 0 0];...
    [0 pi pi+pi/3 pi/3 -pi/3 pi-pi/3 0 0];...
    [pi/3 pi/3 pi pi -pi/3 -pi/3 0 0];...
    [pi/8 pi+pi/8 pi/8+pi/4 pi-pi/8 -pi/8 3/2*pi-pi/8 3/2*pi+pi/8 pi/2+pi/8];...
    [0 pi pi/4 3/4*pi -pi/4 pi+pi/4 3/2*pi pi/2];...
    [pi/4 -pi/4 pi+pi/4 pi-pi/4 -pi/4 pi/4 pi-pi/4 pi+pi/4];...
];

TypeMotorNonVector=int8([3;3;4;4;6;6;6;8;8;8]);

Mb = [0;0;0];
Fb = [0;0;0];
P=wb(1);Q=wb(2);

if uavType==50
    
    Fb(1)=MotorRads(1)+MotorRads(3);
    Mb(3)=MotorRads(1)*0.1-MotorRads(3)*0.1;
    
    return;
end


if uavType<0||uavType>length(TypeMotorNonVector)
    uavType=int8(1);
end

TypeMotorDirVector=TypeMotorDirMatrix(uavType,:);
TypeMotorAngVector=TypeMotorAngMatrix(uavType,:);

for i=1:TypeMotorNonVector(uavType)
    propAng = TypeMotorAngVector(i);
    propdir = TypeMotorDirVector(i);
    PropT = Ct*MotorRads(i)*MotorRads(i);
    PropM = Cm*MotorRads(i)*MotorRads(i);
    
    %Thrust -> Moment
    Mb=Mb+[-R*sin(propAng)*PropT;R*cos(propAng)*PropT;-PropM*propdir];
    
    %gyroscopic moment
    Mb=Mb+[Q*Jm*MotorRads(i)*propdir;-P*Jm*MotorRads(i)*propdir;0];
    
    Fb=Fb+[0;0;-PropT];
end

 
end

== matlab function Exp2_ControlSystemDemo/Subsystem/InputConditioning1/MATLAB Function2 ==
function y = fcn(u)
%将遥控输入的范围控制在1100~1900，同时设置一个死区，死区大小为±deadZone
RCMin = 1100;
RCMax = 1900;
deadZoneRate = 0.05;
deadZone = deadZoneRate*(RCMax-RCMin);
%限幅
if(u < RCMin)
    u = RCMin;
elseif(u > RCMax)
    u = RCMax;
end
%死区
 if(u > 1500+deadZone)
    y = u;
 elseif(u < 1500-deadZone)
     y = u;
 else
     y = 1500;
 end
     
 end

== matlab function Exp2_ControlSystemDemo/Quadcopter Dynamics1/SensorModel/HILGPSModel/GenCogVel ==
function [v,cot] = Ang360(u)
v=norm(u(1:2));

if v < 1
    cot = 0;
else
    cot=atan2d(u(2),u(1));
end
 
if cot<0
    cot=cot+360;
end

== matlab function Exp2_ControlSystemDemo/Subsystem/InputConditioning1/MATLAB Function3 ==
function y = fcn(u)
%将遥控输入的范围控制在1100~1900，同时设置一个死区，死区大小为±deadZone
RCMin = 1100;
RCMax = 1900;
deadZoneRate = 0.05;
deadZone = deadZoneRate*(RCMax-RCMin);
%限幅
if(u < RCMin)
    u = RCMin;
elseif(u > RCMax)
    u = RCMax;
end
%死区
 if(u > 1500+deadZone)
    y = u;
 elseif(u < 1500-deadZone)
     y = u;
 else
     y = 1500;
 end
     
 end

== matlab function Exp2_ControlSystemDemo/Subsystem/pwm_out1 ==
function [M1, M2, M3, M4] = motor_mixer(Roll, Pitch, Yaw, Thrust)

idle_PWM = 1000;

% Quad XROLL （根据QP里面的叉字形结构的文字）
% M1 = ((Pitch+ Yaw)+Thrust-Roll) * 1000 + idle_PWM;
 %M2 = ((Pitch - Yaw)+Thrust+Roll) * 1000 + idle_PWM;
 %M3 = ((Roll +Yaw) + Thrust-Pitch) * 1000 + idle_PWM;
 %M4 = ((-Roll - Pitch-Yaw) + Thrust) * 1000 + idle_PWM;
% M5 = 1000;
% M6 = 1000;
% M7 = 1000;
% M8 = 1000;
%qp上实际的输出
M1 = (Thrust+Pitch-Roll+Yaw) * 1000 + idle_PWM;
 M2 = (Thrust-Pitch +Roll+Yaw) * 1000 + idle_PWM;
 M3 = ( Thrust+Roll+Pitch-Yaw) * 1000 + idle_PWM;
 M4 = (Thrust-Roll- Pitch -Yaw) * 1000 + idle_PWM;
% Quad +
 %M1 = ((Pitch - Yaw) * Thrust / 2 + Thrust) * 1000 + idle_PWM;
 %M2 = ((-Roll + Yaw) * Thrust / 2 + Thrust) * 1000 + idle_PWM;
% M3 = ((-Pitch - Yaw) * Thrust / 2 + Thrust) * 1000 + idle_PWM;
 %M4 = ((Roll + Yaw) * Thrust / 2 + Thrust) * 1000 + idle_PWM;
% M5 = 1000;
% M6 = 1000;
% M7 = 1000;
% M8 = 1000;

% Hex X
% M1 = ((Pitch + Roll / 2 - Yaw) * Thrust / 2 + Thrust) * 1000 + idle_PWM;
% M2 = ((Pitch - Roll / 2 + Yaw) * Thrust / 2 + Thrust) * 1000 + idle_PWM;
% M3 = ((-Roll - Yaw) * Thrust / 2 + Thrust) * 1000 + idle_PWM;
% M4 = ((-Pitch - Roll / 2 + Yaw) * Thrust / 2 + Thrust) * 1000 + idle_PWM;
% M5 = ((-Pitch + Roll / 2 - Yaw) * Thrust / 2 + Thrust) * 1000 + idle_PWM;
% M6 = ((Roll + Yaw) * Thrust / 2 + Thrust) * 1000 + idle_PWM;
% M7 = 1000;
% M8 = 1000;

% Hex X (From Adam)
%M1 = uint16(single(((-Roll - Yaw) * Thrust / 3 + Thrust) * single(1000))) + idle_PWM;
%M2 = uint16(single(((Roll + Yaw) * Thrust / 3 + Thrust) * single(1000))) + idle_PWM;
%M3 = uint16(single(((Pitch + (Roll / 2) - Yaw) * Thrust / 3 + Thrust) * single(1000))) + idle_PWM;
%M4 = uint16(single(((-Pitch - (Roll / 2) + Yaw) * Thrust / 3 + Thrust) * single(1000))) + idle_PWM;
%M5 = uint16(single(((Pitch - (Roll / 2) + Yaw) * Thrust / 3 + Thrust) * single(1000))) + idle_PWM;
%M6 = uint16(single(((-Pitch + (Roll / 2) - Yaw) * Thrust / 3 + Thrust) * single(1000))) + idle_PWM;

% Hex X (Version 2)
% Roll/Yaw
% M1 = ((-Roll - Yaw) * Thrust / 2 + Thrust) * 1000 + idle_PWM;
% M2 = ((Roll + Yaw) * Thrust / 2 + Thrust) * 1000 + idle_PWM;
% % + Pitch/Roll
% M6 = ((Pitch + Roll / 2 - Yaw) * Thrust / 2 + Thrust) * 1000 + idle_PWM;
% M4 = ((Pitch - Roll / 2 + Yaw) * Thrust / 2 + Thrust) * 1000 + idle_PWM;
% % - Pitch/Roll
% M5 = ((-Pitch - Roll / 2 + Yaw) * Thrust / 2 + Thrust) * 1000 + idle_PWM;
% M3 = ((-Pitch + Roll / 2 - Yaw) * Thrust / 2 + Thrust) * 1000 + idle_PWM;

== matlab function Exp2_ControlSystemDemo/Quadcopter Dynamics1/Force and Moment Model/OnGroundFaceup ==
function y = fcn(EulerAng)

targetRoll = 0;
% if cos(EulerAng(1))<0
%     targetRoll=pi;  
% end

targetPitch = 0;
% if cos(EulerAng(2))<0
%         targetPitch=pi;
% end
    
y = [targetRoll;targetPitch;EulerAng(3)];

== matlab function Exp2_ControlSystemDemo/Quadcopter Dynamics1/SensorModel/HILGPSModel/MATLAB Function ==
function FixType = fcn(eph)
if eph <= 2
    FixType=3;
elseif eph <= 4
    FixType=2;
else
    FixType=0;
end

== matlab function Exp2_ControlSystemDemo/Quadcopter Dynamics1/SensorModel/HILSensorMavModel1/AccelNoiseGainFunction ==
function Gain = fcn(theta, ModelParam_noisePowerOnGainAccel, ModelParam_noisePowerOffGainAccel,ModelParam_noisePowerOnGainAccelZ, ModelParam_noisePowerOffGainAccelZ)
%#codegen
if theta>0.1
Gain = [ModelParam_noisePowerOnGainAccel;ModelParam_noisePowerOnGainAccel;ModelParam_noisePowerOnGainAccelZ];
else
    Gain = [ModelParam_noisePowerOffGainAccel;ModelParam_noisePowerOffGainAccel;ModelParam_noisePowerOffGainAccelZ];
end

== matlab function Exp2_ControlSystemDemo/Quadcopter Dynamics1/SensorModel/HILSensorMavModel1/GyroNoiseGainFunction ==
function Gain = fcn(theta, ModelParam_noisePowerOnGainGyro, ModelParam_noisePowerOffGainGyro, ModelParam_noisePowerOnGainGyroZ, ModelParam_noisePowerOffGainGyroZ)
%#codegen
if theta>0.1
    Gain = [ModelParam_noisePowerOnGainGyro;ModelParam_noisePowerOnGainGyro;ModelParam_noisePowerOnGainGyroZ];
else
    Gain = [ModelParam_noisePowerOffGainGyro;ModelParam_noisePowerOffGainGyro;ModelParam_noisePowerOffGainGyroZ];
end

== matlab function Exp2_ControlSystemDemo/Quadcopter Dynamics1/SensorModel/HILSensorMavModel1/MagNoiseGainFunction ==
function Gain = fcn(theta, ModelParam_noisePowerOnGainMag, ModelParam_noisePowerOffGainMag, ModelParam_noisePowerOnGainMagZ, ModelParam_noisePowerOffGainMagZ)
%#codegen
if theta>0.1
    Gain = [ModelParam_noisePowerOnGainMag;ModelParam_noisePowerOnGainMag;ModelParam_noisePowerOnGainMagZ];
else
    Gain = [ModelParam_noisePowerOffGainMag;ModelParam_noisePowerOffGainMag;ModelParam_noisePowerOffGainMagZ];
end

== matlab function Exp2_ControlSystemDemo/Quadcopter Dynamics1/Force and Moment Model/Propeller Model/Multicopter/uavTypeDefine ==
function [n_p,motorPhiVector,motorThetaVector,motorPsiVector,motorRotateDirectionVector]  = fcn(uavType)
% -1: anticlockwise, 1: clockwise 
TypeMotorDirMatrix=[...
    [-1 -1 -1 0 0 0 0 0];... % Tri 3*1 X           Type1
    [1 1 1 0 0 0 0 0];...    % Tri 3*1 +            Type2
    [-1 -1 1 1 0 0 0 0];... % Quad 4*1 X        Type3
    [-1 -1 1 1 0 0 0 0];... % Quad 4*1 +        Type4
    [1 -1 1 -1 -1 1 0 0];... % Hex 6*1 X         Type5
    [1 -1 1 -1 -1 1 0 0];... % Hex 6*1 +         Type6
    [1 -1 1 -1 1 -1 0 0];... % HexCoa 3*2      Type7
    [1 1 -1 -1 -1 -1 1 1];... % Oct 8*1 X        Type8
    [1 1 -1 -1 -1 -1 1 1];... % Oct 8*1 +        Type9
    [1 -1 1 -1 1 -1 1 -1];... % OctCoa 4*2 X  Type10
    [-1 -1 1 1 0 0 0 0];... % Intel Aero          Type11
    [-1 -1 1 1 0 0 0 0];... % custom              Type12
];

TypeMotorPsiAngMatrix=[...
    [pi/3 pi -pi/3 0 0 0 0 0];...%Type1
    [pi/3 pi -pi/3 0 0 0 0 0];...%Type2
    [pi/4   pi/4+pi     pi/4+3*pi/2     pi/4+pi/2   0 0 0 0];...%Type3
    [pi/2 3*pi/2 0 pi 0 0 0 0];...%Type4
    [pi/2 3/2*pi 3/2*pi+pi/3 pi/2+pi/3 pi/2-pi/3 3/2*pi-pi/3 0 0];...%Type5
    [0 pi pi+pi/3 pi/3 -pi/3 pi-pi/3 0 0];...%Type6
    [pi/3 pi/3 pi pi -pi/3 -pi/3 0 0];...%Type7
    [pi/8 pi+pi/8 pi/8+pi/4 pi-pi/8 -pi/8 3/2*pi-pi/8 3/2*pi+pi/8 pi/2+pi/8];...%Type8
    [0 pi pi/4 3/4*pi -pi/4 pi+pi/4 3/2*pi pi/2];...%Type9
    [pi/4 -pi/4 pi+pi/4 pi-pi/4 -pi/4 pi/4 pi-pi/4 pi+pi/4];...%Type10
    [43*pi/180     223*pi/180      317*pi/180      137*pi/180     0 0 0 0];...%Type11  Intel Aero
    [pi/4   pi/4+pi     pi/4+3*pi/2     pi/4+pi/2   0 0 0 0];...%Type12  custom
];

TypeMotorThetaAngMatrix=[...
    [0 0 0 0 0 0 0 0];...%Type1
    [0 0 0 0 0 0 0 0];...%Type2
    [0 0 0 0 0 0 0 0];...%Type3
    [0 0 0 0 0 0 0 0];...%Type4
    [0 0 0 0 0 0 0 0];...%Type5
    [0 0 0 0 0 0 0 0];...%Type6
    [0 0 0 0 0 0 0 0];...%Type7
    [0 0 0 0 0 0 0 0];...%Type8
    [0 0 0 0 0 0 0 0];...%Type9
    [0 0 0 0 0 0 0 0];...%Type10
    [0 0 0 0 0 0 0 0];...%Type11
    [pi/4   pi/4    pi/4    pi/4    0 0 0 0];...%Type12
    ];
TypeMotorPhiAngMatrix=[...
    [0 0 0 0 0 0 0 0];...%Type1
    [0 0 0 0 0 0 0 0];...%Type2
    [0 0 0 0 0 0 0 0];...%Type3
    [0 0 0 0 0 0 0 0];...%Type4
    [0 0 0 0 0 0 0 0];...%Type5
    [0 0 0 0 0 0 0 0];...%Type6
    [0 0 0 0 0 0 0 0];...%Type7
    [0 0 0 0 0 0 0 0];...%Type8
    [0 0 0 0 0 0 0 0];...%Type9
    [0 0 0 0 0 0 0 0];...%Type10
    [0 0 0 0 0 0 0 0];...%Type11
    [0 0 0 0 0 0 0 0];...%Type12
];

TypeMotorNonVector=int8([3;3;4;4;6;6;6;8;8;8;4;4]);

if uavType<0||uavType>length(TypeMotorNonVector)
    uavType=int8(1);
end

motorRotateDirectionVector=TypeMotorDirMatrix(uavType,:);
motorPsiVector=TypeMotorPsiAngMatrix(uavType,:);
motorThetaVector=TypeMotorThetaAngMatrix(uavType,:);
motorPhiVector=TypeMotorPhiAngMatrix(uavType,:);
n_p = TypeMotorNonVector(uavType);

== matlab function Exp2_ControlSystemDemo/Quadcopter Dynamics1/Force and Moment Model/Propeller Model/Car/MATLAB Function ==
function [Fb,Mb] = fcn(MotorRads)

Mb = [0;0;0];
Fb = [0;0;0];

Fb(1)=MotorRads(1)+MotorRads(3);
Mb(3)=MotorRads(1)*0.1-MotorRads(3)*0.1;

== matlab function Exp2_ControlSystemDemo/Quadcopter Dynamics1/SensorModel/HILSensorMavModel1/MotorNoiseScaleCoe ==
function NoiseScaleCoe = fcn(PWMin)
%本函数输一个分段函数，分为三段三段斜率不同，具体形状可以通过修改下面四个参数设置

%如何设置合理参数使得噪声在此分段函数前提下更加真实  
%1、首先采集实际飞行过程中飞机的噪声水平然后修改噪声模块的幅值
%2、飞机静止时的噪声则可以通过设置keyPoint1的数值，也就是本分段函数的自变量值为0时候的函数值来调整静止时候飞机传感器噪声

%分段函数有两个起点和转折点，下面四个点一次对应起点两个拐点终点，第一个数表示和坐标的数值，第二个表示对应的函数值
%默认  输入为1是函数值也是1
keyPoint1 = [0 0.05];%不要修改 数字0
keyPoint2 = [0.8 1];
keyPoint3 = [1.7 1];
keyPoint4 = [2 2];%不要修改

%m 范围 0-2 50%油门时候为 m = 1
m = 2*mean(PWMin);
if m <keyPoint2(1)
    NoiseScaleCoe = ((keyPoint2(2) - keyPoint1(2))/(keyPoint2(1)-keyPoint1(1)))*(m - keyPoint1(1)) + keyPoint1(2);
else
    if m > keyPoint2(1) && m < keyPoint3(1)
        NoiseScaleCoe = ((keyPoint3(2) - keyPoint2(2))/(keyPoint3(1)-keyPoint2(1)))*(m - keyPoint2(1)) + keyPoint2(2);
    else
        NoiseScaleCoe = ((keyPoint4(2) - keyPoint3(2))/(keyPoint4(1)-keyPoint3(1)))*(m - keyPoint3(1)) + keyPoint3(2);
    end
end

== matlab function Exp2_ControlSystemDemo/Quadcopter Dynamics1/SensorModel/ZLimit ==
function Xee = fcn(zt,xe)
Xee=xe;
if Xee(3)>zt
    Xee(3)=zt;
end

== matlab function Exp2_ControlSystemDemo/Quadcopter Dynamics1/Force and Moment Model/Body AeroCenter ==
function [Fd,Md] = fcn(wb,Vb,Cd, CCm, uavDearo)
% This is control effectiveness model, where Fb is the force produced by motors, Mb is
% the moment produced by motors, and Fd is the resistance produced by the air.
% The gyroscopic torque is not considered here.
% uavDearo 机身重心位置，向下为正

 Fd = -Cd*Vb.*abs(Vb);%
 
 Mfd=[Fd(2)*uavDearo;-Fd(1)*uavDearo;0];
 
Md=-CCm.*wb.*abs(wb);
Md=Mfd+Md;
%  CCm=4.72e-3;
%  Md=-CCm*wb.*abs(wb)*0.5;%0.3
%  Md= Mfd+Md;
 
end
